# ET6801 register map
Vendor: ETMCU Inc.; File version: v0.0.1
CPU: CM7 r2p1, little endian, MPU, FPU, I-cache, D-cache, ITCM, DTCM, 4 interrupt priority bits
Registers are 32-bit, read-write, reset 0x0 unless marked. A register's access mark holds for its fields unless they carry their own. Offsets are from the block's base; [hi:lo] are bit positions; {n}, {i} and the like mark numbered series; <NAME> marks a mode.

## SYSC — Provide an overview of the purpose and functionality of the peripheral: sysc
Base 0x40400000
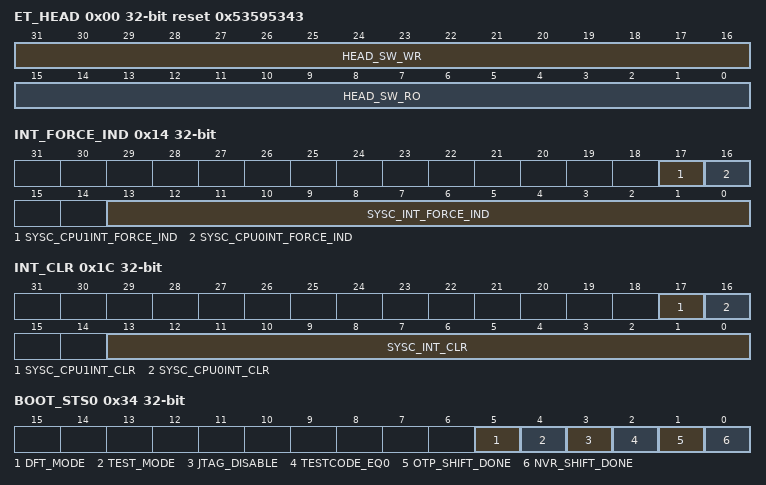
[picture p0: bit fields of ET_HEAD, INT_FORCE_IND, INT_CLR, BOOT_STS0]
0x00 ET_HEAD reset 0x53595343
  [31:16] HEAD_SW_WR — 软件测试读写寄存器，硬件无访问
  [15:0] HEAD_SW_RO ro — 软件只读上报寄存器，硬件无访问, SYSC的ASICII 码表示
0x04 INT_EN
  [13:0] SYSC_INT_EN — b0：取消使能SYSC逻辑中断； 'b1：表示使能SYSC逻辑中断； [0] :osc0_25m_los [1] :osc1_25m_los [2]:xo25m_los [3]:pll0_los [4]:pll0_unlock [5]:a2d_pmu_borh [6]:a2d_pmu_borh_warn [7]:a2d_pmu_ovrh [8]:a2d_pmu_borl [9]:a2d_pmu_borl_warn [10]:a2d_pmu_ovrl [11]:a2d_pmu_sysldo_ocp [12]:a2d_tsd_sync [13]:a2d_tsd_warn
0x08 CMPC_INT_EN
  [21:0] CMPC_INT_EN — b0：取消使能cmpc逻辑中断； 'b1：表示使能cpmc逻辑中断； [10]~[0]: cmpc_h_lpm_wkup10~cmpc_h_lpm_wkup0 [21]~[11]:cmpc_l_lpm_wkup10~cmpc_l_lpm_wkup0
0x0C INT_MASK
  [13:0] SYSC_INT_MASK — b0：取消屏蔽SYSC逻辑中断； 'b1：表示屏蔽SYSC逻辑中断； [0] :osc0_25m_los [1] :osc1_25m_los [2]:xo25m_los [3]:pll0_los [4]:pll0_unlock [5]:a2d_pmu_borh [6]:a2d_pmu_borh_warn [7]:a2d_pmu_ovrh [8]:a2d_pmu_borl [9]:a2d_pmu_borl_warn [10]:a2d_pmu_ovrl [11]:a2d_pmu_sysldo_ocp [12]:a2d_tsd_sync [13]:a2d_tsd_warn
0x10 CMPC_INT_MASK
  [21:0] CMPC_INT_MASK — b0：取消屏蔽CMPC逻辑中断； 'b1：表示屏蔽CMPC逻辑中断； [10]~[0]: cmpc_h_lpm_wkup10~cmpc_h_lpm_wkup0 [21]~[11]:cmpc_l_lpm_wkup10~cmpc_l_lpm_wkup0
0x14 INT_FORCE_IND
  [17] SYSC_CPU1INT_FORCE_IND — b1：表示强制产生相应的cpu1中断，硬件自清零
  [16] SYSC_CPU0INT_FORCE_IND — b1：表示强制产生相应的cpu0中断，硬件自清零
  [13:0] SYSC_INT_FORCE_IND — b1：表示强制产生相应的测试中断，硬件自清零 [0] :osc0_25m_los [1] :osc1_25m_los [2]:xo25m_los [3]:pll0_los [4]:pll0_unlock [5]:a2d_pmu_borh [6]:a2d_pmu_borh_warn [7]:a2d_pmu_ovrh [8]:a2d_pmu_borl [9]:a2d_pmu_borl_warn [10]:a2d_pmu_ovrl [11]:a2d_pmu_sysldo_ocp [12]:a2d_tsd_sync [13]:a2d_tsd_warn
0x18 CMPC_INT_FORCE_IND
  [21:0] CMPC_INT_FORCE_IND — b1：表示软件强制置起CMPC逻辑中断，硬件自清零； [10]~[0]: cmpc_h_lpm_wkup10~cmpc_h_lpm_wkup0 [21]~[11]:cmpc_l_lpm_wkup10~cmpc_l_lpm_wkup0
0x1C INT_CLR
  [17] SYSC_CPU1INT_CLR — b1：表示清除相应的cpu1中断状态，硬件自清零
  [16] SYSC_CPU0INT_CLR — b1：表示清除相应的cpu0中断状态，硬件自清零
  [13:0] SYSC_INT_CLR — b1：表示清除相应的中断状态，硬件自清零 [0] :osc0_25m_los [1] :osc1_25m_los [2]:xo25m_los [3]:pll0_los [4]:pll0_unlock [5]:a2d_pmu_borh [6]:a2d_pmu_borh_warn [7]:a2d_pmu_ovrh [8]:a2d_pmu_borl [9]:a2d_pmu_borl_warn [10]:a2d_pmu_ovrl [11]:a2d_pmu_sysldo_ocp [12]:a2d_tsd_sync [13]:a2d_tsd_warn
0x20 CMPC_INT_CLR
  [21:0] CMPC_INT_CLR — b1：表示清除相应的中断状态，硬件自清零 [10]~[0]: cmpc_h_lpm_wkup10~cmpc_h_lpm_wkup0 [21]~[11]:cmpc_l_lpm_wkup10~cmpc_l_lpm_wkup0
0x24 INT_RAW_RPT ro
  [13:0] SYSC_INT_RAW_RPT — 中断MASK前RAW 中断状态上报 'b0：表示中断MASK前无中断状态； 'b1：表示中断MASK前有中断状态； [0] :osc0_25m_los [1] :osc1_25m_los [2]:xo25m_los [3]:pll0_los [4]:pll0_unlock [5]:a2d_pmu_borh [6]:a2d_pmu_borh_warn [7]:a2d_pmu_ovrh [8]:a2d_pmu_borl [9]:a2d_pmu_borl_warn [10]:a2d_pmu_ovrl [11]:a2d_pmu_sysldo_ocp [12]:a2d_tsd_sync [13]:a2d_tsd_warn
0x28 CMPC_INT_RAW_RPT ro
  [21:0] CMPC_INT_RAW_RPT — 中断MASK前RAW 中断状态上报 'b0：表示中断MASK前无中断状态； 'b1：表示中断MASK前有中断状态； [0] :osc0_25m_los [1] :osc1_25m_los [2]:xo25m_los [3]:pll0_los [4]:pll0_unlock [5]:a2d_pmu_borh [6]:a2d_pmu_borh_warn [7]:a2d_pmu_ovrh [8]:a2d_pmu_borl [9]:a2d_pmu_borl_warn [10]:a2d_pmu_ovrl [11]:a2d_pmu_sysldo_ocp [12]:a2d_tsd_sync [13]:a2d_tsd_warn
0x2C INT_STATUS_RPT ro
  [13:0] SYSC_INT_STATUS_RPT — 中断MASK后中断状态上报 'b0：表示中断MASK后无中断状态； 'b1：表示中断MASK后有中断状态； [0] :osc0_25m_los [1] :osc1_25m_los [2]:xo25m_los [3]:pll0_los [4]:pll0_unlock [5]:a2d_pmu_borh [6]:a2d_pmu_borh_warn [7]:a2d_pmu_ovrh [8]:a2d_pmu_borl [9]:a2d_pmu_borl_warn [10]:a2d_pmu_ovrl [11]:a2d_pmu_sysldo_ocp [12]:a2d_tsd_sync [13]:a2d_tsd_warn
0x30 CMPC_INT_STATUS_RPT ro
  [21:0] CMPC_INT_STATUS_RPT — 中断MASK后中断状态上报 'b0：表示中断MASK后无中断状态； 'b1：表示中断MASK后有中断状态； [10]~[0]: cmpc_h_lpm_wkup10~cmpc_h_lpm_wkup0 [21]~[11]:cmpc_l_lpm_wkup10~cmpc_l_lpm_wkup0
0x34 BOOT_STS0 ro
  [5] DFT_MODE — 内部锁存后的dft_mode数据上报
  [4] TEST_MODE — 内部锁存后的test_mode数据上报
  [3] JTAG_DISABLE — 内部锁存后的jtag_disable数据上报
  [2] TESTCODE_EQ0 — 内部锁存后的testcode_eq0数据上报
  [1] OTP_SHIFT_DONE — 内部锁存后的otp_shift_done数据上报
  [0] NVR_SHIFT_DONE — 内部锁存后的nvr_shift_done数据上报
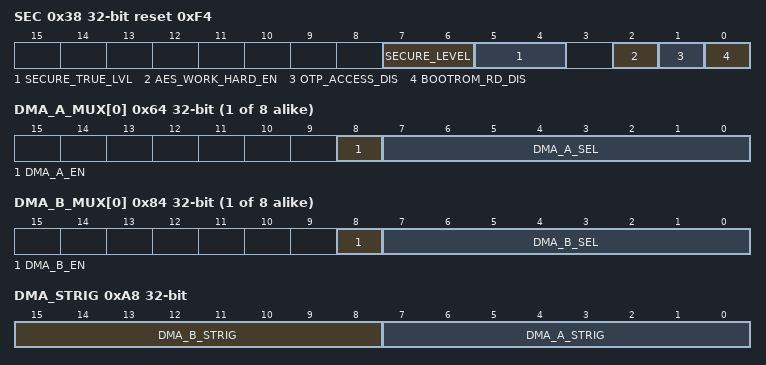
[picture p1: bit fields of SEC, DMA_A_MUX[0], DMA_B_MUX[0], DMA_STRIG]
0x38 SEC reset 0xF4
  [7:6] SECURE_LEVEL ro — otp输入的鉴权等级 2'b11:无需鉴权 2’b10/2’b01：需要鉴权，鉴权后所有调试接口都可访问 2’b00：禁止访问，所有调试接口都不可访问
  [5:4] SECURE_TRUE_LVL ro — 最终鉴权等级，根据test_code和secure_level得到： test_code != 32'b0 ： secure_true_lvl == 'b11； test_code == 32'b0 ： secure_true_lvl == secure_level； 2'b11:无需鉴权 2’b10/2’b01：需要鉴权，鉴权后所有调试接口都可访问 2’b00：禁止访问，所有调试接口都不可访问
  [2] AES_WORK_HARD_EN — 当boot程序自行判断AES是否需要关闭，在boot程序最后配置该寄存器；'b0: AES模块不能被访问；'b1: AES模块可以被正常访问； 该信号只能被写0，不能被写1；
  [1] OTP_ACCESS_DIS — 当boot程序自行判断otp信息在应用程序是否可以被操作（读/写/擦除），在boot程序最后配置该寄存器；'b0: otp信息能被操作（读/写/擦除）；'b1: otp信息不能被操作（读/写/擦除），读的时候返回固定值0； 该信号只能被写1，不能被写0；
  [0] BOOTROM_RD_DIS — 当boot程序检测到OTP信息：bootrom_rdp==1'b1 && test_code==32'd0，配置该寄存器为1；'b0: bootrom空间可以被正常访问；'b1: bootrom空间不被访问，输出被钳位到32'd0； 该信号只能被写1，不能被写0；
{0x3C+4i} CHIP_DIE{i} (i=0..7)
  [31:0] INFO — 芯片die参数信息[{32i+31}:{32i}]；bootrom从otp回读后写到该寄存器内，写操作受bootrom_rd_dis控制；
0x5C CHIP_VERSION0
  [31:0] PARTID — 芯片CHIP VERSION配置寄存器，仅bootrom阶段可写，硬件无任何操作
0x60 CHIP_VERSION1
  [31:0] PARTID — 芯片CHIP VERSION配置寄存器，仅bootrom阶段可写，硬件无任何操作
{0x64+4i} DMA_A_MUX[{i}] (i=0..7) — DMA_A_MUX%S
  [8] DMA_A_EN — AHB DMA0子通道的DMA选择使能 'b0：当前通道关闭选择使能，相应的dma_req和dma_single恒为0； 'b1：当前通道启用选择使能，按软件配置选择dma_req和dma_single输出。
  [7:0] DMA_A_SEL — AHB DMA0子通道的DMA选择： 0crc_dma_req 1fmac_rd_dma_req 2fmac_wr_dma_req 6~3sdfm0_dma_req[3:0] 10~7sdfm1_dma_req[3:0] 14~11sdfm2_dma_req[3:0] 18~15sdfm3_dma_req[3:0] 36~19epwm_dma_req[17:0] 37~54reserved 66~55 etim_dma_req[11:0] 70~67sarc0_dma_req[3:0] 71ADCAEVT 75~72sarc1_dma_req[3:0] 76ADCBEVT 80~77sarc2_dma_req[3:0] 81ADCCEVT 82cmpc0_dma_dac0_req 83cmpc0_dma_dac1_req 84cmpc1_dma_dac0_req 85cmpc1_dma_dac1_req 86cmpc2_dma_dac0_req 87cmpc2_dma_dac1_req 88cmpc3_dma_dac0_req 89cmpc3_dma_dac1_req 90cmpc4_dma_dac0_req 91cmpc4_dma_dac1_req 92cmpc5_dma_dac0_req 93cmpc5_dma_dac1_req 94cmpc6_dma_dac0_req 95cmpc6_dma_dac1_req 96cmpc7_dma_dac0_req 97cmpc7_dma_dac1_req 98cmpc8_dma_dac0_req 99cmpc8_dma_dac1_req 100cmpc9_dma_dac0_req 101cmpc9_dma_dac1_req 102cmpc10_dma_dac0_req 103cmpc10_dma_dac1_req 104stm0_dma_req 105stm1_dma_req 106stm2_dma_req 107stm3_dma_req 108stm4_dma_req 109stm5_dma_req 110bdac0_dma_req 111bdac1_dma_req 112aes_wr_dma_req 113aes_rd_dma_req 114wag_dma_req 115XINT0 116XINT1 117XINT2 118XINT3 119XINT4 120CLB0_INT 121CLB1_INT 122CLB2_INT 123CLB3_INT 124CLB4_INT 125CLB5_INT 126LIN0_TXDMA 127LIN0_RXDMA 128LIN1_TXDMA 129LIN1_RXDMA 130-191reserved 192uart0_dma_tx_req 193uart0_dma_rx_req 194uart1_dma_tx_req 195uart1_dma_rx_req 196uart2_dma_tx_req 197uart2_dma_rx_req 198uart3_dma_tx_req 199uart3_dma_rx_req 200uart4_dma_tx_req 201uart4_dma_rx_req 202uart5_dma_tx_req 203uart5_dma_rx_req 204uart6_dma_tx_req 205uart6_dma_rx_req 206uart7_dma_tx_req 207uart7_dma_rx_req 208i2c0_dma_tx_req 209i2c0_dma_rx_req 210i2c1_dma_tx_req 211i2c1_dma_rx_req 212i2c2_dma_tx_req 213i2c2_dma_rx_req 214spi0_dma_tx_req 215spi0_dma_rx_req 216spi1_dma_tx_req 217spi1_dma_rx_req 218spi2_dma_tx_req 219spi2_dma_rx_req 220spi3_dma_tx_req 221spi3_dma_rx_req 222can0_dma_tx_req 223can0_dma_rx_req 224can1_dma_tx_req 225can1_dma_rx_req 226can2_dma_tx_req 227can2_dma_rx_req 228qspi_dma_tx_req 229qspi_dma_rx_req 230~255reserved
{0x84+4i} DMA_B_MUX[{i}] (i=0..7) — DMA_B_MUX%S
  [8] DMA_B_EN — AHB DMA1子通道的DMA选择使能 'b0：当前通道关闭选择使能，相应的dma_req和dma_single恒为0； 'b1：当前通道启用选择使能，按软件配置选择dma_req和dma_single输出。
  [7:0] DMA_B_SEL — AHB DMA1子通道的DMA选择，其选项与CFG_DMA_A_MUX [cfg_dma_a_sel]的选项一致。
0xA4 DMA_MUX_MK reset 0xFFFF
  [15:0] DMA_MUX_FIN_MSK — 每个bit对应一个DMA通道，BIT0对应AHB DMA0的通道0，......，BIT7对应AHB DMA0的通道7，BIT8对应AHB DMA1的通道0，......，BIT15对应AHB DMA1的通道7； 'b0：使用dma_ack和dma_finish信号联合控制DMA传输，支持一次hac （寄存器读写）dma触发，响应多个dma_ack，实现多个burst传输（直至出现dma_finish）； 'b1：屏蔽dma_finish信号，仅使用dma_ack信号控制DMA传输，一次触发，仅响应一次dma_ack信号（ET6001模式）
0xA8 DMA_STRIG
  [15:8] DMA_B_STRIG wo — 软件置1强制DMA1 8通道进行一次触发,硬件自清零，该触发功能与cfg_dma_b_sel选择后的触发信号功能相同，注意：若cfg_dma_b_sel配置大于191，则强制触发无效。 cfg_dma_b_strig[7:0]分别对应DMA1的7~0通道；
  [7:0] DMA_A_STRIG wo — 软件置1强制DMA0 8通道进行一次触发,硬件自清零，该触发功能与cfg_dma_a_sel0~7选择后的触发信号功能相同。注意：若cfg_dma_b_sel配置大于191，则强制触发无效。 cfg_dma_a_strig[7:0]分别对应DMA0的7~0通道；
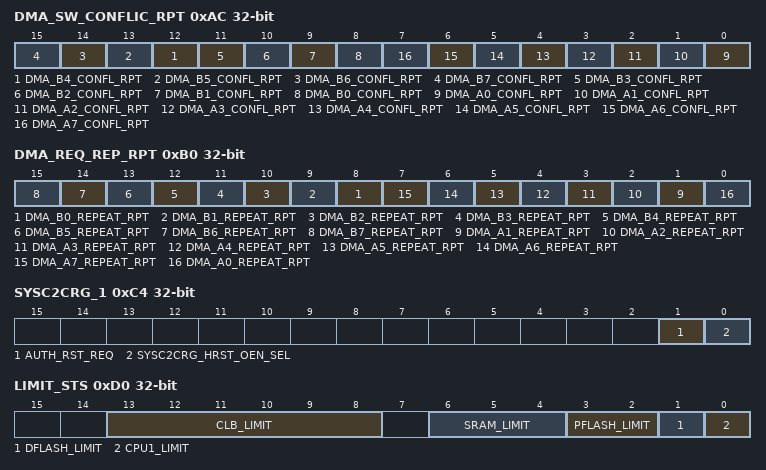
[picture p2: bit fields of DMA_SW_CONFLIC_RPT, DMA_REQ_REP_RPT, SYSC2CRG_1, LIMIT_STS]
0xAC DMA_SW_CONFLIC_RPT
  [n+8] DMA_B{n}_CONFL_RPT (n=4..7) — AHB DMA1的{n}通道，切换DMA选择时，dma_req或dma_single为高，当前状态寄存器置1，写1清，软件做调试用 软件写1清。
  [11] DMA_B3_CONFL_RPT — AHB DMA0的3通道，切换DMA选择时，dma_req或dma_single为高，当前状态寄存器置1，写1清，软件做调试用 软件写1清。
  [10] DMA_B2_CONFL_RPT — AHB DMA1的2通道，切换DMA选择时，dma_req或dma_single为高，当前状态寄存器置1，写1清，软件做调试用 软件写1清。
  [9] DMA_B1_CONFL_RPT — AHB DMA1的1通道，切换DMA选择时，dma_req或dma_single为高，当前状态寄存器置1，写1清，软件做调试用 软件写1清。
  [8] DMA_B0_CONFL_RPT — AHB DMA1的0通道，切换DMA选择时，dma_req或dma_single为高，当前状态寄存器置1，写1清，软件做调试用 软件写1清。
  [n] DMA_A{n}_CONFL_RPT (n=0..7) — AHB DMA0的{n}通道，切换DMA选择时，dma_req或dma_single为高，当前状态寄存器置1，写1清，软件做调试用 软件写1清。
0xB0 DMA_REQ_REP_RPT
  [n+8] DMA_B{n}_REPEAT_RPT (n=0..7) — AHB DMA1的{n}通道，在一次HAC的DMA请求未结束前，又出现新的HAC DMA请求触发源，则当前寄存器位锁存为高电平，软件写1清。
  [n] DMA_A{n}_REPEAT_RPT (n=1..7) — AHB DMA0的{n}通道，在一次HAC的DMA请求未结束前，又出现新的HAC DMA请求触发源，则当前寄存器位锁存为高电平，软件写1清。
  [0] DMA_A0_REPEAT_RPT — AHB DMA0的0通道，在一次HAC的DMA请求未结束前，又出现新的HAC DMA请求触发源，则当前寄存器位锁存为高电平，软件写1清。当前寄存器地址中，含repeat字样的重复告警上报只针对cfg_dma_a/b_sel的取值大于等于19，小于等于129的场景（HAC进行寄存器读写的场景）。
0xB4 CPU0_BTADDR reset 0x20500000
  [31:0] SYSC_CPU0_INITVTOR — CPU0启动地址
0xB8 CPU1_BTADDR
  [31:0] SYSC_CPU1_INITVTOR — CPU1启动地址
0xBC NV
  [31:0] LOCK — POR时钟域关键寄存器锁定使能；当配置为非0x12345678时，可上锁对特定寄存器的配置；
0xC0 SYSC2CRG
  [31:0] SOFTRST_N — 全局软复位；当配置为0x45670123时，产生全局软复位信号（1'b0，低电平有效）到CRG模块，CRG随机进行芯片全局软复位；CRG进行全局软复位后，该配置自动被清成default值，也就是全局软复位信号被复位成1'b1:
0xC4 SYSC2CRG_1
  [1] AUTH_RST_REQ — jauth模块的软复位请求信号。1'b1:软复位请求有效 1'b0:软复位请求无效
  [0] SYSC2CRG_HRST_OEN_SEL — 选择芯片的POR复位和WDG复位输出到芯片HRD_RST_N管脚可观测，其观测值是否有效。 1'b0:观测值有效 1'b1:观测值无效
0xC8 SYSC2SPWM
  [17:0] BC_MAP_INFO — spwm扩展配置映射信息；18bit配置对应18个spwm，如bit[0]对应spwm0，bit[1]对应spwm1......bit[17]对应spwm17; 'b0：在配置spwm_bc时，不会同时配置到该spwm； 'b1：在配置spwm_bc时，会同时配置到该spwm； 准静态配置：该配置完成后，spwm才可能打开使能进行工作；
0xCC BOOT
  [0] PROC_IND — 启动过程说明； 'b0：冷启动； 'b1：热启动； bootrom根据这个bit来判断走冷启动流程还是热启动流程，在bootrom的最后，将该bit修改为1；
0xD0 LIMIT_STS ro
  [13:8] CLB_LIMIT — 信号含义，clb内共有6个clb_title，每个bit表示一个clb的clb_title使能，1表示使能，0表示不使能：clb_limit[0]:clb_title0的使能； clb_limit[1]:clb_title1的使能； clb_limit[2]:clb_title2的使能； clb_limit[3]:clb_title3的使能； clb_limit[4]:clb_title4的使能； clb_limit[5]:clb_title5的使能；
  [6:4] SRAM_LIMIT — 寄存器含义： 3'b000:SRAM256KB+256KB 3'b001:SRAM 128KB+128KB others：SRAM 256KB + 256KB注意：sram在各个限制模式下，起始地址均是0x2040_0000 不限定模式下： SRAM0起始地址0x2040_0000； SRAM1起始地址0x2044_0000； 限定模式下： SRAM0起始地址0x2040_0000； SRAM1起始地址0x2042_0000；
  [3:2] PFLASH_LIMIT — 信号含义： 2'b00:pflash空间2MB空间不做空间访问限制； 2'b01:pflash 空间限制为1MB； 2'b10:pflash 空间限制为512KB; others:pflash 空间不限制，为2MB; 注意：pflash限定与否，起始地址不变，软件看到的pflash系统地址起始地址都是0x8000_0000
  [1] DFLASH_LIMIT — 信号含义： 1'b0:dflash main 空间128KB总线不做访问限制； 1'b1:dflash main 空间128KB总线限制访问注意：dflash限定与否，其起始地址均不变，均为0x0808_0000
  [0] CPU1_LIMIT — 信号含义： 1'b0:cpu1 限定； 1'b1:cpu1 不限定；
{0xD4+4i} BLBX{i} (i=0..15)
  [31:0] REG_BX — 黑匣子寄存器，只可CPU读写，POR复位；硬件无任何操作；受sysc_nv_lock寄存器锁定；
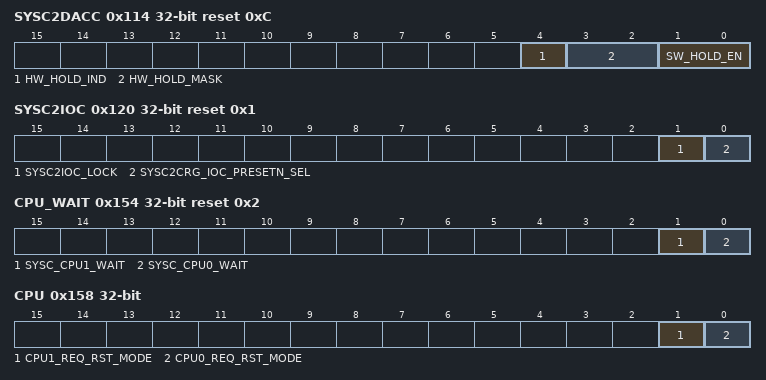
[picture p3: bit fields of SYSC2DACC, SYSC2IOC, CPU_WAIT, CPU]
0x114 SYSC2DACC reset 0xC
  [4] HW_HOLD_IND — DAC输出保持状态； 'b0：DAC输出正常，根据DAC配置进行输出； 'b1：DAC输出保持不变；软复位重新启动，APP程序需要根据软硬件hold_ind判断是否进行重新配置DAC参数，以及对hold_ind进行清零；软件写1清。
  [3:2] HW_HOLD_MASK — DACC硬件保持屏蔽信号； 'b0：DACC硬件保持屏蔽功能关闭； 'b1：DACC硬件保持屏蔽功能打开； 受sysc_nv_lock寄存器锁定；
  [1:0] SW_HOLD_EN — DACC软件强制保持使能； 'b0：DACC软件强制保持使能关闭； 'b1：DACC软件强制保持使能打开； 受sysc_nv_lock寄存器锁定；
0x118 FLS
  [0] BANKSWAP — Pflash高低地址映射内容调换选择； 'b0:不调换； 'b1:调换； 根据LIMIT_STS.pflash_limits完成高低地址内容调换，如在不限定方案表达的含义为： ‘b0:正常使用pflash的2M地址空间； ’b1：pflash的高1M地址空间与低1M空间调换； 每次复位，BOOTROM从dFlash NVR读取对应信息，写到这个寄存器；
0x11C EFC
  [1:0] DPD — 对EFC的Flash颗粒进行DPD控制；bit[0]对应pflash-efc1，bit[1]对应dflash-efc2，bit[2]对应efc2； 'b0：Flash颗粒正常工作； 'b1：Flash颗粒工作到DPD模式；
0x120 SYSC2IOC reset 0x1
  [1] SYSC2IOC_LOCK — IOC的配置lock指示； 'b0: IOC可以正常配置； 'b1: IOC不能被配置；
  [0] SYSC2CRG_IOC_PRESETN_SEL — IOC 复位选择 'b0 -- 受sys复位（包含por复位） 'b1 -- 仅受por复位
0x124 CLK_SCNT
  [0] SEL_IN — syscnt时钟选择信号 'b0：内部选择后的osc25M时钟；（默认） 'b1：XO25M时钟；
0x128 SCNT
  [0] HALT_MODE_EN — syscnt halt模式使能； 'b0：syscnt halt模式使能关闭； 'b1：syscnt halt模式使能打开；
{0x12C+4i} STM{i} ro (i=0..5)
  [31:0] SYSC_ERG_CNT — 紧急故障触发源锁定当前STM{i}值
0x144 CHIP_RSVED_0
  [31:0] SYS — 预留寄存器配置，给软件使用，硬件不做处理, 当前寄存器表示对应bit[31:0]；
0x148 CHIP_RSVED_1
  [31:0] SYS — 预留寄存器配置，给软件使用，硬件不做处理, 当前寄存器表示对应bit[63:32]；
0x14C CHIP_RSVED_1_0
  [31:0] POR — 预留寄存器配置，给软件使用，硬件不做处理, 当前寄存器表示对应bit[31:0]；
0x150 CHIP_RSVED_1_1
  [31:0] POR — 预留寄存器配置，给软件使用，硬件不做处理, 当前寄存器表示对应bit[63:32]；
0x154 CPU_WAIT reset 0x2
  [1] SYSC_CPU1_WAIT — CPU1wait设置 'b1:cpu1处于wait状态 ‘b0：cpu1不处于wait状态
  [0] SYSC_CPU0_WAIT — CPU0wait设置 'b1:cpu0处于wait状态 ‘b0：cpu0不处于wait状态
0x158 CPU
  [1] CPU1_REQ_RST_MODE — CPU复位申请，产生哪种模式的复位； 'b0：产生全局软复位； 'b1：只产生CPU1系统复位
  [0] CPU0_REQ_RST_MODE — CPU复位申请，产生哪种模式的复位； 'b0：产生全局软复位； 'b1：只产生CPU0系统复位
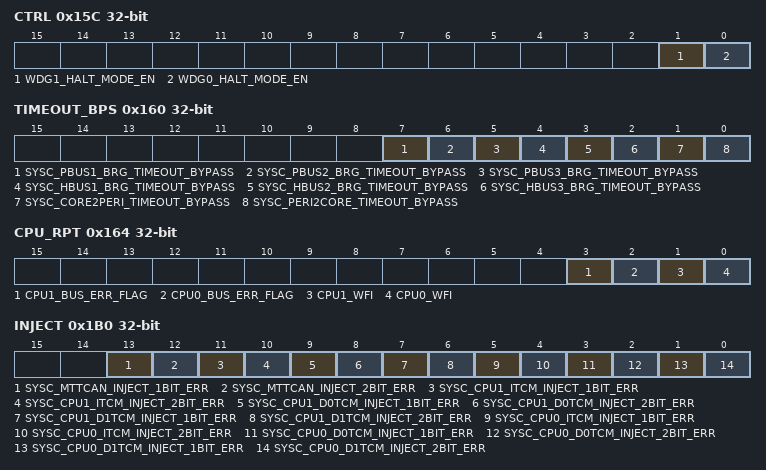
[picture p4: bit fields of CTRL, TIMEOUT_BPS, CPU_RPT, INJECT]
0x15C CTRL
  [1] WDG1_HALT_MODE_EN — 看门狗1的halt模式使能开关； 'b0：看门狗0的halt模式使能关闭； 'b1：看门狗0的halt模式使能打开；
  [0] WDG0_HALT_MODE_EN — 看门狗0的halt模式使能开关； 'b0：看门狗0的halt模式使能关闭； 'b1：看门狗0的halt模式使能打开；
0x160 TIMEOUT_BPS
  [7] SYSC_PBUS1_BRG_TIMEOUT_BYPASS — APB BUS1的timeout旁路使能开关； 'b0：APB BUS1的timeout旁路使能关闭； 'b1：APB BUS1的timeout旁路使能打开；
  [6] SYSC_PBUS2_BRG_TIMEOUT_BYPASS — APB BUS2的timeout旁路使能开关； 'b0：APB BUS2的timeout旁路使能关闭； 'b1：APB BUS2的timeout旁路使能打开；
  [5] SYSC_PBUS3_BRG_TIMEOUT_BYPASS — APB BUS3的timeout旁路使能开关； 'b0：APB BUS3的timeout旁路使能关闭； 'b1：APB BUS3的timeout旁路使能打开；
  [4] SYSC_HBUS1_BRG_TIMEOUT_BYPASS — AHB BUS1的timeout旁路使能开关； 'b0：AHB BUS1的timeout旁路使能关闭； 'b1：AHB BUS1的timeout旁路使能打开；
  [3] SYSC_HBUS2_BRG_TIMEOUT_BYPASS — AHB BUS2的timeout旁路使能开关； 'b0：AHB BUS2的timeout旁路使能关闭； 'b1：AHB BUS2的timeout旁路使能打开；
  [2] SYSC_HBUS3_BRG_TIMEOUT_BYPASS — AHB BUS3的timeout旁路使能开关； 'b0：AHB BUS3的timeout旁路使能关闭； 'b1：AHB BUS3的timeout旁路使能打开；
  [1] SYSC_CORE2PERI_TIMEOUT_BYPASS — core2peri的timeout旁路使能开关； 'b0：core2peri的timeout旁路使能关闭； 'b1：core2peri的timeout旁路使能打开；
  [0] SYSC_PERI2CORE_TIMEOUT_BYPASS — peri2core的timeout旁路使能开关； 'b0：AHB BUS3的timeout旁路使能关闭； 'b1：AHB BUS3的timeout旁路使能打开；
0x164 CPU_RPT ro
  [3] CPU1_BUS_ERR_FLAG — CPU1的总线错误状态 'b0：cpu1不处于总线错误状态； 'b1：cpu1处于总线错误状态；
  [2] CPU0_BUS_ERR_FLAG — CPU0的总线错误状态； 'b0：cpu0不处于总线错误状态； 'b1：cpu0处于总线错误状态；
  [1] CPU1_WFI — CPU1的wfi状态； 'b0：cpu不处于wfi状态； 'b1：cpu处于wfi状态；
  [0] CPU0_WFI — CPU的wfi状态； 'b0：cpu不处于wfi状态； 'b1：cpu处于wfi状态；
0x168 CTRLBUS_0 reset 0x9A9D1
  [31:0] SYSC_XSRAM0_CTRLBUS — 1rw类型sram, 当前寄存器表示对应bit[31:0]；
0x16C CTRLBUS_1
  [31:0] SYSC_XSRAM0_CTRLBUS — 1rw类型sram, 当前寄存器表示对应bit[63:32]；
0x170 CTRLBUS_1_0 reset 0x9A9D1
  [31:0] SYSC_XSRAM1_CTRLBUS — 1rw类型sram, 当前寄存器表示对应bit[31:0]；
0x174 CTRLBUS_1_1
  [31:0] SYSC_XSRAM1_CTRLBUS — 1rw类型sram, 当前寄存器表示对应bit[63:32]；
0x178 CTRLBUS_2_0 reset 0x9A9D1
  [31:0] SYSC_BOOTROM_CTRLBUS — rom类型, 当前寄存器表示对应bit[31:0]；
0x17C CTRLBUS_2_1
  [31:0] SYSC_BOOTROM_CTRLBUS — rom类型, 当前寄存器表示对应bit[63:32]；
0x180 CTRLBUS_3_0 reset 0x9A9D1
  [31:0] SYSC_CAN_MSG_CTRLBUS — 1rw类型sram, 当前寄存器表示对应bit[31:0]；
0x184 CTRLBUS_3_1
  [31:0] SYSC_CAN_MSG_CTRLBUS — 1rw类型sram, 当前寄存器表示对应bit[63:32]；
{0x168+8i} CTRLBUS_{i}_0 reset 0x9A9D1 (i=4..6)
  [31:0] SYSC_SARC{i-4}_CTRLBUS — 1r1w/1rw类型sram, 当前寄存器表示对应bit[31:0]；
{0x16C+8i} CTRLBUS_{i}_1 (i=4..6)
  [31:0] SYSC_SARC{i-4}_CTRLBUS — 1r1w/1rw类型sram, 当前寄存器表示对应bit[63:32]；
0x1A0 CTRLBUS_7_0 reset 0x9A9D1
  [31:0] SYSC_FMAC_CTRLBUS — 1rw类型sram, 当前寄存器表示对应bit[31:0]；
0x1A4 CTRLBUS_7_1
  [31:0] SYSC_FMAC_CTRLBUS — 1rw类型sram, 当前寄存器表示对应bit[63:32]；
0x1A8 CTRLBUS_8_0 reset 0x9A9D1
  [31:0] SYSC_ETF_CTRLBUS — 1rw类型sram, 当前寄存器表示对应bit[31:0]；
0x1AC CTRLBUS_8_1
  [31:0] SYSC_ETF_CTRLBUS — 1rw类型sram, 当前寄存器表示对应bit[63:32]；
0x1B0 INJECT
  [13] SYSC_MTTCAN_INJECT_1BIT_ERR — CAN的ECC 1bit错误注入配置 'b0： 不注入； 'b1： 注入1bit错误；
  [12] SYSC_MTTCAN_INJECT_2BIT_ERR — CAN的ECC 2bit错误注入配置 'b0： 不注入； 'b1： 注入1bit错误；
  [11] SYSC_CPU1_ITCM_INJECT_1BIT_ERR — cpu itcm的ECC 1bit错误注入配置 'b0： 不注入； 'b1： 注入1bit错误；
  [10] SYSC_CPU1_ITCM_INJECT_2BIT_ERR — cpu itcm的ECC 2bit错误注入配置 'b0： 不注入； 'b1： 注入1bit错误；
  [9] SYSC_CPU1_D0TCM_INJECT_1BIT_ERR — cpu d0tcm的ECC 1bit错误注入配置 'b0： 不注入； 'b1： 注入1bit错误；
  [8] SYSC_CPU1_D0TCM_INJECT_2BIT_ERR — cpu d0tcm的ECC 2bit错误注入配置 'b0： 不注入； 'b1： 注入1bit错误；
  [7] SYSC_CPU1_D1TCM_INJECT_1BIT_ERR — cpu d1tcm的ECC 1bit错误注入配置 'b0： 不注入； 'b1： 注入1bit错误；
  [6] SYSC_CPU1_D1TCM_INJECT_2BIT_ERR — cpu d1tcm的ECC 2bit错误注入配置 'b0： 不注入； 'b1： 注入1bit错误；
  [5] SYSC_CPU0_ITCM_INJECT_1BIT_ERR — cpu itcm的ECC 1bit错误注入配置 'b0： 不注入； 'b1： 注入1bit错误；
  [4] SYSC_CPU0_ITCM_INJECT_2BIT_ERR — cpu itcm的ECC 2bit错误注入配置 'b0： 不注入； 'b1： 注入1bit错误；
  [3] SYSC_CPU0_D0TCM_INJECT_1BIT_ERR — cpu d0tcm的ECC 1bit错误注入配置 'b0： 不注入； 'b1： 注入1bit错误；
  [2] SYSC_CPU0_D0TCM_INJECT_2BIT_ERR — cpu d0tcm的ECC 2bit错误注入配置 'b0： 不注入； 'b1： 注入1bit错误；
  [1] SYSC_CPU0_D1TCM_INJECT_1BIT_ERR — cpu d1tcm的ECC 1bit错误注入配置 'b0： 不注入； 'b1： 注入1bit错误；
  [0] SYSC_CPU0_D1TCM_INJECT_2BIT_ERR — cpu d1tcm的ECC 2bit错误注入配置 'b0： 不注入； 'b1： 注入1bit错误；
0x1B4 ECCEN
  [0] SYSC_MTTCAN_ECC_EN — CAN0的ECC 使能配置 'b0： ECC不使能； 'b1： ECC使能；
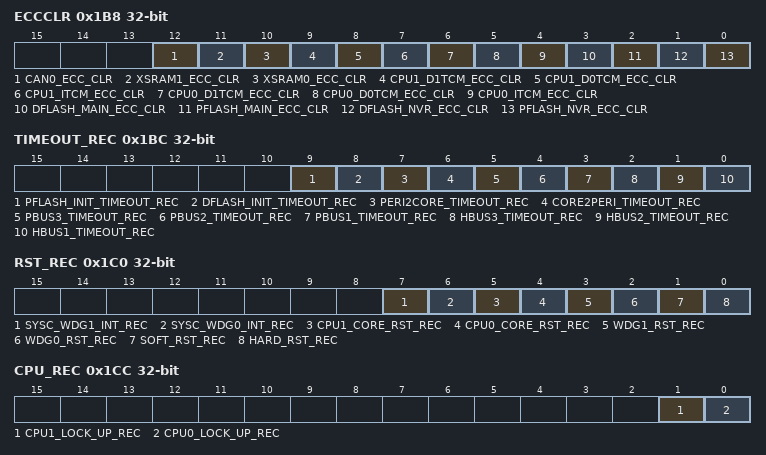
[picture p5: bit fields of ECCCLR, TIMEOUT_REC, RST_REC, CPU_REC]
0x1B8 ECCCLR
  [12] CAN0_ECC_CLR — can0 ECC错误指示清零信号，同时清零2bit错误和1bit错误'b0：ECC错误指示不做清零动作； 'b1：ECC错误指示清零动作， 硬件会对本控制bit自动清零；
  [11] XSRAM1_ECC_CLR — sram1 ECC错误指示清零信号，同时清零2bit错误和1bit错误 'b0：ECC错误指示不做清零动作； 'b1：ECC错误指示清零动作， 硬件会对本控制bit自动清零；
  [10] XSRAM0_ECC_CLR — sram0 ECC错误指示清零信号，同时清零2bit错误和1bit错误 'b0：ECC错误指示不做清零动作； 'b1：ECC错误指示清零动作， 硬件会对本控制bit自动清零；
  [9] CPU1_D1TCM_ECC_CLR — CPU d1tcm ECC错误指示清零信号，同时清零2bit错误和1bit错误 'b0：ECC错误指示不做清零动作； 'b1：ECC错误指示清零动作， 硬件会对本控制bit自动清零；
  [8] CPU1_D0TCM_ECC_CLR — CPU d0tcm ECC错误指示清零信号，同时清零2bit错误和1bit错误 'b0：ECC错误指示不做清零动作； 'b1：ECC错误指示清零动作， 硬件会对本控制bit自动清零；
  [7] CPU1_ITCM_ECC_CLR — CPU itcm ECC错误指示清零信号，同时清零2bit错误和1bit错误 'b0：ECC错误指示不做清零动作； 'b1：ECC错误指示清零动作， 硬件会对本控制bit自动清零；
  [6] CPU0_D1TCM_ECC_CLR — CPU d1tcm ECC错误指示清零信号，同时清零2bit错误和1bit错误 'b0：ECC错误指示不做清零动作； 'b1：ECC错误指示清零动作， 硬件会对本控制bit自动清零；
  [5] CPU0_D0TCM_ECC_CLR — CPU d0tcm ECC错误指示清零信号，同时清零2bit错误和1bit错误'b0：ECC错误指示不做清零动作；'b1：ECC错误指示清零动作，硬件会对本控制bit自动清零；
  [4] CPU0_ITCM_ECC_CLR — CPU itcm ECC错误指示清零信号，同时清零2bit错误和1bit错误 'b0：ECC错误指示不做清零动作； 'b1：ECC错误指示清零动作， 硬件会对本控制bit自动清零；
  [3] DFLASH_MAIN_ECC_CLR — EFC2 Main ECC错误指示清零信号，同时清零2bit错误和1bit错误 'b0：ECC错误指示不做清零动作； 'b1：ECC错误指示清零动作，硬件会对本控制bit自动清零；
  [2] PFLASH_MAIN_ECC_CLR — EFC0 Main ECC错误指示清零信号，同时清零2bit错误和1bit错误'b0：ECC错误指示不做清零动作；'b1：ECC错误指示清零动作，硬件会对本控制bit自动清零；
  [1] DFLASH_NVR_ECC_CLR — EFC2 NVR ECC错误指示清零信号，同时清零2bit错误和1bit错误 'b0：ECC错误指示不做清零动作； 'b1：ECC错误指示清零动作， 硬件会对本控制bit自动清零；
  [0] PFLASH_NVR_ECC_CLR — EFC1 NVR ECC错误指示清零信号，同时清零2bit错误和1bit错误 'b0：ECC错误指示不做清零动作； 'b1：ECC错误指示清零动作，硬件会对本控制bit自动清零；
0x1BC TIMEOUT_REC
  [9] PFLASH_INIT_TIMEOUT_REC — PFlash0初始化失败记录； 'b0：没有发生过PFlash0初始化失败； 'b1：发生过PFlash0初始化失败； 软件对本bit域写1，表示清除该历史记录；软件写1清。
  [8] DFLASH_INIT_TIMEOUT_REC — DFlash初始化失败记录； 'b0：没有发生过DFlash初始化失败； 'b1：发生过DFlash初始化失败； 软件对本bit域写1，表示清除该历史记录；软件写1清。
  [7] PERI2CORE_TIMEOUT_REC — peri2core_timeout历史记录； 'b0：没有发生过peri2core timeout； 'b1：发生过peri2core timeout； 软件对本bit域写1，表示清除该历史记录；软件写1清。
  [6] CORE2PERI_TIMEOUT_REC — core2peri_timeout历史记录； 'b0：没有发生过core2peri timeout； 'b1：发生过core2peri timeout； 软件对本bit域写1，表示清除该历史记录；软件写1清。
  [5] PBUS3_TIMEOUT_REC — pbus3_timeout历史记录； 'b0：没有发生过pbus3 timeout； 'b1：发生过pbus3 timeout； 软件对本bit域写1，表示清除该历史记录；软件写1清。
  [4] PBUS2_TIMEOUT_REC — pbus2_timeout历史记录； 'b0：没有发生过pbus2 timeout； 'b1：发生过pbus2 timeout； 软件对本bit域写1，表示清除该历史记录；软件写1清。
  [3] PBUS1_TIMEOUT_REC — pbus1_timeout历史记录； 'b0：没有发生过pbus1 timeout； 'b1：发生过pbus1 timeout； 软件对本bit域写1，表示清除该历史记录；软件写1清。
  [2] HBUS3_TIMEOUT_REC — hbus3_timeout历史记录；'b0：没有发生过hbus3 timeout；'b1：发生过hbus3 timeout；软件对本bit域写1，表示清除该历史记录；软件写1清。
  [1] HBUS2_TIMEOUT_REC — hbus2_timeout历史记录； 'b0：没有发生过hbus2 timeout； 'b1：发生过hbus2 timeout； 软件对本bit域写1，表示清除该历史记录；软件写1清。
  [0] HBUS1_TIMEOUT_REC — hbus1_timeout历史记录；'b0：没有发生过hbus1 timeout；'b1：发生过hbus1 timeout；软件对本bit域写1，表示清除该历史记录；软件写1清。
0x1C0 RST_REC
  [7] SYSC_WDG1_INT_REC — 看门狗1中断历史记录； 'b0：没有发生过看门狗1中断； 'b1：发生过看门狗1中断； 软件对本bit域写1，表示清除该历史记录；软件写1清。
  [6] SYSC_WDG0_INT_REC — 看门狗0中断历史记录； 'b0：没有发生过看门狗0中断； 'b1：发生过看门狗0中断； 软件对本bit域写1，表示清除该历史记录；软件写1清。
  [5] CPU1_CORE_RST_REC — CPU1复位请求历史记录； 'b0：没有发生过CPU1复位请求； 'b1：发生过CPU1复位请求； 软件对本bit域写1，表示清除该历史记录；软件写1清。
  [4] CPU0_CORE_RST_REC — CPU0复位请求历史记录； 'b0：没有发生过CPU0复位请求； 'b1：发生过CPU0复位请求； 软件对本bit域写1，表示清除该历史记录；软件写1清。
  [3] WDG1_RST_REC — 看门狗1复位请求历史记录； 'b0：没有发生过看门狗1复位请求； 'b1：发生过看门狗1复位请求； 软件对本bit域写1，表示清除该历史记录；软件写1清。
  [2] WDG0_RST_REC — 看门狗0复位请求历史记录； 'b0：没有发生过看门狗0复位请求； 'b1：发生过看门狗0复位请求； 软件对本bit域写1，表示清除该历史记录；软件写1清。
  [1] SOFT_RST_REC — 全局软复位历史记录； 'b0：没有发生过全局软复位； 'b1：发生过全局软复位； 软件对本bit域写1，表示清除该历史记录；软件写1清。
  [0] HARD_RST_REC — 管脚复位历史记录； 'b0：没有发生过管脚硬复位； 'b1：发生过管脚硬复位； 软件对本bit域写1，表示清除该历史记录；软件写1清。
0x1C4 FLS_REC ro
  [23:0] DFLASH_STATE_REC — DFlash状态机信息，该信息是使用dflash_init_timeout锁存的状态信息。芯片内部debug信息。
0x1C8 FLS_REC_1 ro
  [23:0] PFLASH_STATE_REC — PFlash0状态机信息，该信息是使用pflash0_init_timeout锁存的状态信息。
0x1CC CPU_REC
  [1] CPU1_LOCK_UP_REC — CPU1死锁状态记录； 'b0：没有发生过CPU1死锁； 'b1：发生过CPU1死锁； 软件对本bit域写1，表示清除该历史记录； 软件写1清。
  [0] CPU0_LOCK_UP_REC — CPU0死锁状态记录； 'b0：没有发生过CPU0死锁； 'b1：发生过CPU0死锁； 软件对本bit域写1，表示清除该历史记录； 软件写1清。
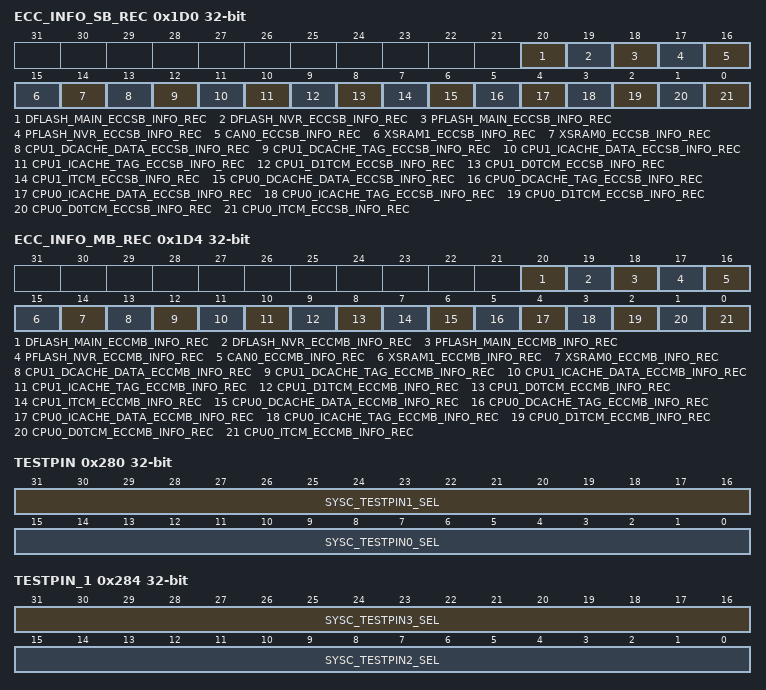
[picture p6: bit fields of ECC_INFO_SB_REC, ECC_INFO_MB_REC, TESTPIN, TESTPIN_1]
0x1D0 ECC_INFO_SB_REC ro
  [20] DFLASH_MAIN_ECCSB_INFO_REC — DFlash main array ECC信息历史记录，单比特错误； 'b0：没有发生过ECC错误； 'b1：发生过ECC错误；对应ecc_clr配置才能清除该历史记录；
  [19] DFLASH_NVR_ECCSB_INFO_REC — Flash NVR ECC信息历史记录，单比特错误； 'b0：没有发生过ECC错误； 'b1：发生过ECC错误； 对应ecc_clr配置才能清除该历史记录；
  [18] PFLASH_MAIN_ECCSB_INFO_REC — PFlash0 main array ECC信息历史记录，单比特错误； 'b0：没有发生过ECC错误； 'b1：发生过ECC错误； 对应ecc_clr配置才能清除该历史记录；
  [17] PFLASH_NVR_ECCSB_INFO_REC — Flash NVR ECC信息历史记录，单比特错误； 'b0：没有发生过ECC错误； 'b1：发生过ECC错误； 对应ecc_clr配置才能清除该历史记录；
  [16] CAN0_ECCSB_INFO_REC — AXI SRAM0 ECC信息历史记录，单比特错误； 'b0：没有发生过ECC错误； 'b1：发生过ECC错误； 对应ecc_clr配置才能清除该历史记录；
  [15] XSRAM1_ECCSB_INFO_REC — AXI SRAM1 ECC信息历史记录，单比特错误； 'b0：没有发生过ECC错误； 'b1：发生过ECC错误； 对应ecc_clr配置才能清除该历史记录；
  [14] XSRAM0_ECCSB_INFO_REC — AXI SRAM0 ECC信息历史记录，单比特错误； 'b0：没有发生过ECC错误； 'b1：发生过ECC错误；对应ecc_clr配置才能清除该历史记录；
  [13] CPU1_DCACHE_DATA_ECCSB_INFO_REC — CPU1 DCACHE data ECC信息状态记录，单比特错误；
  [12] CPU1_DCACHE_TAG_ECCSB_INFO_REC — CPU1 DCACHE TAG ECC信息状态记录，单比特错误；
  [11] CPU1_ICACHE_DATA_ECCSB_INFO_REC — CPU1 ICACHE data ECC信息状态记录，单比特错误；
  [10] CPU1_ICACHE_TAG_ECCSB_INFO_REC — CPU1 ICACHE TAG ECC信息状态记录，单比特错误；
  [9] CPU1_D1TCM_ECCSB_INFO_REC — cpu1 D1TCM ECC信息历史记录，单比特错误； 'b0：没有发生过ECC错误； 'b1：发生过ECC错误； 对应ecc_clr配置才能清除该历史记录；
  [8] CPU1_D0TCM_ECCSB_INFO_REC — cpu1 D0TCM ECC信息历史记录，单比特错误； 'b0：没有发生过ECC错误； 'b1：发生过ECC错误； 对应ecc_clr配置才能清除该历史记录；
  [7] CPU1_ITCM_ECCSB_INFO_REC — cpu1 ITCM ECC信息历史记录，单比特错误； 'b0：没有发生过ECC错误； 'b1：发生过ECC错误； 对应ecc_clr配置才能清除该历史记录；
  [6] CPU0_DCACHE_DATA_ECCSB_INFO_REC — CPU0 DCACHE data ECC信息状态记录，单比特错误；
  [5] CPU0_DCACHE_TAG_ECCSB_INFO_REC — CPU0 DCACHE TAG ECC信息状态记录，单比特错误；
  [4] CPU0_ICACHE_DATA_ECCSB_INFO_REC — CPU0 ICACHE data ECC信息状态记录，单比特错误；
  [3] CPU0_ICACHE_TAG_ECCSB_INFO_REC — CPU0 ICACHE TAG ECC信息状态记录，单比特错误；
  [2] CPU0_D1TCM_ECCSB_INFO_REC — CPU0 D1TCM ECC信息历史记录，单比特错误； 'b0：没有发生过ECC错误； 'b1：发生过ECC错误； 对应ecc_clr配置才能清除该历史记录；
  [1] CPU0_D0TCM_ECCSB_INFO_REC — CPU0 D0TCM ECC信息历史记录，单比特错误； 'b0：没有发生过ECC错误； 'b1：发生过ECC错误； 对应ecc_clr配置才能清除该历史记录；
  [0] CPU0_ITCM_ECCSB_INFO_REC — CPU0 ITCM ECC信息历史记录，单比特错误； 'b0：没有发生过ECC错误； 'b1：发生过ECC错误； 对应ecc_clr配置才能清除该历史记录；
0x1D4 ECC_INFO_MB_REC ro
  [20] DFLASH_MAIN_ECCMB_INFO_REC — DFlash main array ECC信息历史记录，多比特错误； 'b0：没有发生过ECC错误； 'b1：发生过ECC错误； 对应ecc_clr配置才能清除该历史记录；
  [19] DFLASH_NVR_ECCMB_INFO_REC — Flash NVR ECC信息历史记录，多比特错误； 'b0：没有发生过ECC错误； 'b1：发生过ECC错误； 对应ecc_clr配置才能清除该历史记录；
  [18] PFLASH_MAIN_ECCMB_INFO_REC — PFlash0 main array ECC信息历史记录，多比特错误； 'b0：没有发生过ECC错误； 'b1：发生过ECC错误； 对应ecc_clr配置才能清除该历史记录；
  [17] PFLASH_NVR_ECCMB_INFO_REC — Flash NVR ECC信息历史记录，多比特错误； 'b0：没有发生过ECC错误； 'b1：发生过ECC错误； 对应ecc_clr配置才能清除该历史记录；
  [16] CAN0_ECCMB_INFO_REC — AXI SRAM0 ECC信息历史记录，多比特错误；'b0：没有发生过ECC错误；'b1：发生过ECC错误；对应ecc_clr配置才能清除该历史记录；
  [15] XSRAM1_ECCMB_INFO_REC — AXI SRAM1 ECC信息历史记录，多比特错误； 'b0：没有发生过ECC错误； 'b1：发生过ECC错误； 对应ecc_clr配置才能清除该历史记录；
  [14] XSRAM0_ECCMB_INFO_REC — AXI SRAM0 ECC信息历史记录，多比特错误； 'b0：没有发生过ECC错误； 'b1：发生过ECC错误； 对应ecc_clr配置才能清除该历史记录；
  [13] CPU1_DCACHE_DATA_ECCMB_INFO_REC — CPU1 DCACHE data ECC信息状态记录，多比特错误；
  [12] CPU1_DCACHE_TAG_ECCMB_INFO_REC — CPU1 DCACHE TAG ECC信息状态记录，多比特错误；
  [11] CPU1_ICACHE_DATA_ECCMB_INFO_REC — CPU1 ICACHE data ECC信息状态记录，多比特错误；
  [10] CPU1_ICACHE_TAG_ECCMB_INFO_REC — CPU1 ICACHE TAG ECC信息状态记录，多比特错误；
  [9] CPU1_D1TCM_ECCMB_INFO_REC — cpu1 D1TCM ECC信息历史记录，多比特错误； 'b0：没有发生过ECC错误； 'b1：发生过ECC错误； 对应ecc_clr配置才能清除该历史记录；
  [8] CPU1_D0TCM_ECCMB_INFO_REC — cpu1 D0TCM ECC信息历史记录，多比特错误；'b0：没有发生过ECC错误；'b1：发生过ECC错误；对应ecc_clr配置才能清除该历史记录；
  [7] CPU1_ITCM_ECCMB_INFO_REC — cpu1 ITCM ECC信息历史记录，多比特错误； 'b0：没有发生过ECC错误； 'b1：发生过ECC错误； 对应ecc_clr配置才能清除该历史记录；
  [6] CPU0_DCACHE_DATA_ECCMB_INFO_REC — CPU0 DCACHE data ECC信息状态记录，多比特错误；
  [5] CPU0_DCACHE_TAG_ECCMB_INFO_REC — CPU0 DCACHE TAG ECC信息状态记录，多比特错误；
  [4] CPU0_ICACHE_DATA_ECCMB_INFO_REC — CPU0 ICACHE data ECC信息状态记录，多比特错误；
  [3] CPU0_ICACHE_TAG_ECCMB_INFO_REC — CPU0 ICACHE TAG ECC信息状态记录，多比特错误；
  [2] CPU0_D1TCM_ECCMB_INFO_REC — CPU0 D1TCM ECC信息历史记录，多比特错误； 'b0：没有发生过ECC错误； 'b1：发生过ECC错误； 对应ecc_clr配置才能清除该历史记录；
  [1] CPU0_D0TCM_ECCMB_INFO_REC — CPU0 D0TCM ECC信息历史记录，多比特错误； 'b0：没有发生过ECC错误； 'b1：发生过ECC错误； 对应ecc_clr配置才能清除该历史记录；
  [0] CPU0_ITCM_ECCMB_INFO_REC — CPU0 ITCM ECC信息历史记录，多比特错误； 'b0：没有发生过ECC错误； 'b1：发生过ECC错误； 对应ecc_clr配置才能清除该历史记录；
0x1D8 ECC_ADDR_SB_REC ro
  [31:0] CPU0_ITCM_ECCSB_ADDR_REC — CPU itcm ECC单比特错误地址，锁定第一次上报值
0x1DC ECC_ADDR_SB_REC_1 ro
  [31:0] CPU0_D0TCM_ECCSB_ADDR_REC — CPU d0tcm ECC单比特错误地址，锁定第一次上报值
0x1E0 ECC_ADDR_SB_REC_2 ro
  [31:0] CPU0_D1TCM_ECCSB_ADDR_REC — CPU d1tcm ECC单比特错误地址，锁定第一次上报值
0x1E4 ECC_ADDR_SB_REC_3 ro
  [31:0] CPU0_ICACHE_TAG_ECCSB_ADDR_REC — CPU icache ECC单bit错误地址，只有22bit有效，且cache无法区分tag/data；锁定第一次上报值；
0x1E8 ECC_ADDR_SB_REC_4 ro
  [31:0] CPU0_ICACHE_DATA_ECCSB_ADDR_REC — CPU icache ECC单bit错误地址，只有22bit有效，且cache无法区分tag/data；锁定第一次上报值；
0x1EC ECC_ADDR_SB_REC_5 ro
  [31:0] CPU0_DCACHE_TAG_ECCSB_ADDR_REC — CPU dcache ECC单bit错误地址，只有22bit有效，且cache无法区分tag/data；锁定第一次上报值；
0x1F0 ECC_ADDR_SB_REC_6 ro
  [31:0] CPU0_DCACHE_DATA_ECCSB_ADDR_REC — CPU dcache ECC单bit错误地址，只有22bit有效，且cache无法区分tag/data；锁定第一次上报值；
0x1F4 ECC_ADDR_SB_REC_7 ro
  [31:0] CPU1_ITCM_ECCSB_ADDR_REC — CPU itcm ECC单比特错误地址，锁定第一次上报值
0x1F8 ECC_ADDR_SB_REC_8 ro
  [31:0] CPU1_D0TCM_ECCSB_ADDR_REC — CPU d0tcm ECC单比特错误地址，锁定第一次上报值
0x1FC ECC_ADDR_SB_REC_9 ro
  [31:0] CPU1_D1TCM_ECCSB_ADDR_REC — CPU d1tcm ECC单比特错误地址，锁定第一次上报值
0x200 ECC_ADDR_SB_REC_10 ro
  [31:0] CPU1_ICACHE_TAG_ECCSB_ADDR_REC — CPU icache ECC单bit错误地址，只有22bit有效，且cache无法区分tag/data；锁定第一次上报值；
0x204 ECC_ADDR_SB_REC_11 ro
  [31:0] CPU1_ICACHE_DATA_ECCSB_ADDR_REC — CPU icache ECC单bit错误地址，只有22bit有效，且cache无法区分tag/data；锁定第一次上报值；
0x208 ECC_ADDR_SB_REC_12 ro
  [31:0] CPU1_DCACHE_TAG_ECCSB_ADDR_REC — CPU dcache ECC单bit错误地址，只有22bit有效，且cache无法区分tag/data；锁定第一次上报值；
0x20C ECC_ADDR_SB_REC_13 ro
  [31:0] CPU1_DCACHE_DATA_ECCSB_ADDR_REC — CPU dcache ECC单bit错误地址，只有22bit有效，且cache无法区分tag/data；锁定第一次上报值；
0x210 ECC_ADDR_SB_REC_14 ro
  [31:0] XSRAM0_ECCSB_ADDR_REC — SRAM0 ECC单比特错误地址，锁定第一次上报值
0x214 ECC_ADDR_SB_REC_15 ro
  [31:0] XSRAM1_ECCSB_ADDR_REC — SRAM1 ECC单比特错误地址，锁定第一次上报值
0x218 ECC_ADDR_SB_REC_16 ro
  [31:0] CAN0_ECCSB_ADDR_REC — CAN0 ECC单比特错误地址，锁定第一次上报值
0x21C ECC_ADDR_SB_REC_17 ro
  [31:0] DFLASH_NVR_ECCSB_ADDR_REC — dFlash NVR ECC单比特错误地址，锁定第一次上报值
0x220 ECC_ADDR_SB_REC_18 ro
  [31:0] DFLASH_MAIN_ECCSB_ADDR_REC — dFlash Main ECC单比特错误地址，锁定第一次上报值
0x224 ECC_ADDR_SB_REC_19 ro
  [31:0] PFLASH_NVR_ECCSB_ADDR_REC — pFlash0 NVR ECC单比特错误地址，锁定第一次上报值
0x228 ECC_ADDR_SB_REC_20 ro
  [31:0] PFLASH_MAIN_ECCSB_ADDR_REC — pFlash0 Main ECC单比特错误地址，锁定第一次上报值
0x22C ECC_ADDR_MB_REC ro
  [31:0] CPU0_ITCM_ECCMB_ADDR_REC — CPU itcm ECC多比特错误地址，锁定第一次上报值
0x230 ECC_ADDR_MB_REC_1 ro
  [31:0] CPU0_D0TCM_ECCMB_ADDR_REC — CPU d0tcm ECC多比特错误地址，锁定第一次上报值
0x234 ECC_ADDR_MB_REC_2 ro
  [31:0] CPU0_D1TCM_ECCMB_ADDR_REC — CPU d1tcm ECC多比特错误地址，锁定第一次上报值
0x238 ECC_ADDR_MB_REC_3 ro
  [31:0] CPU0_ICACHE_TAG_ECCMB_ADDR_REC — CPU icache ECC单bit错误地址，只有22bit有效，且cache无法区分tag/data；锁定第一次上报值；
0x23C ECC_ADDR_MB_REC_4 ro
  [31:0] CPU0_ICACHE_DATA_ECCMB_ADDR_REC — CPU icache ECC单bit错误地址，只有22bit有效，且cache无法区分tag/data；锁定第一次上报值；
0x240 ECC_ADDR_MB_REC_5 ro
  [31:0] CPU0_DCACHE_TAG_ECCMB_ADDR_REC — CPU dcache ECC单bit错误地址，只有22bit有效，且cache无法区分tag/data；锁定第一次上报值；
0x244 ECC_ADDR_MB_REC_6 ro
  [31:0] CPU0_DCACHE_DATA_ECCMB_ADDR_REC — CPU dcache ECC单bit错误地址，只有22bit有效，且cache无法区分tag/data；锁定第一次上报值；
0x248 ECC_ADDR_MB_REC_7 ro
  [31:0] CPU1_ITCM_ECCMB_ADDR_REC — CPU itcm ECC多比特错误地址，锁定第一次上报值
0x24C ECC_ADDR_MB_REC_8 ro
  [31:0] CPU1_D0TCM_ECCMB_ADDR_REC — CPU d0tcm ECC多比特错误地址，锁定第一次上报值
0x250 ECC_ADDR_MB_REC_9 ro
  [31:0] CPU1_D1TCM_ECCMB_ADDR_REC — CPU d1tcm ECC多比特错误地址，锁定第一次上报值
0x254 ECC_ADDR_MB_REC_10 ro
  [31:0] CPU1_ICACHE_TAG_ECCMB_ADDR_REC — CPU icache ECC单bit错误地址，只有22bit有效，且cache无法区分tag/data；锁定第一次上报值；
0x258 ECC_ADDR_MB_REC_11 ro
  [31:0] CPU1_ICACHE_DATA_ECCMB_ADDR_REC — CPU icache ECC单bit错误地址，只有22bit有效，且cache无法区分tag/data；锁定第一次上报值；
0x25C ECC_ADDR_MB_REC_12 ro
  [31:0] CPU1_DCACHE_TAG_ECCMB_ADDR_REC — CPU dcache ECC单bit错误地址，只有22bit有效，且cache无法区分tag/data；锁定第一次上报值；
0x260 ECC_ADDR_MB_REC_13 ro
  [31:0] CPU1_DCACHE_DATA_ECCMB_ADDR_REC — CPU dcache ECC单bit错误地址，只有22bit有效，且cache无法区分tag/data；锁定第一次上报值；
0x264 ECC_ADDR_MB_REC_14 ro
  [31:0] XSRAM0_ECCMB_ADDR_REC — SRAM0 ECC多比特错误地址，锁定第一次上报值
0x268 ECC_ADDR_MB_REC_15 ro
  [31:0] XSRAM1_ECCMB_ADDR_REC — SRAM1 ECC多比特错误地址，锁定第一次上报值
0x26C ECC_ADDR_MB_REC_16 ro
  [31:0] CAN0_ECCMB_ADDR_REC — CAN0 ECC多比特错误地址，锁定第一次上报值
0x270 ECC_ADDR_MB_REC_17 ro
  [31:0] DFLASH_NVR_ECCMB_ADDR_REC — dFlash NVR ECC多比特错误地址，锁定第一次上报值
0x274 ECC_ADDR_MB_REC_18 ro
  [31:0] DFLASH_MAIN_ECCMB_ADDR_REC — dFlash Main ECC多比特错误地址，锁定第一次上报值
0x278 ECC_ADDR_MB_REC_19 ro
  [31:0] PFLASH_NVR_ECCMB_ADDR_REC — pFlash0 NVR ECC多比特错误地址，锁定第一次上报值
0x27C ECC_ADDR_MB_REC_20 ro
  [31:0] PFLASH_MAIN_ECCMB_ADDR_REC — pFlash0 Main ECC多比特错误地址，锁定第一次上报值
0x280 TESTPIN
  [31:16] SYSC_TESTPIN1_SEL — 功能模式各模块测试管脚选择
  [15:0] SYSC_TESTPIN0_SEL — 功能模式各模块测试管脚选择
0x284 TESTPIN_1
  [31:16] SYSC_TESTPIN3_SEL — 功能模式各模块测试管脚选择
  [15:0] SYSC_TESTPIN2_SEL — 功能模式各模块测试管脚选择
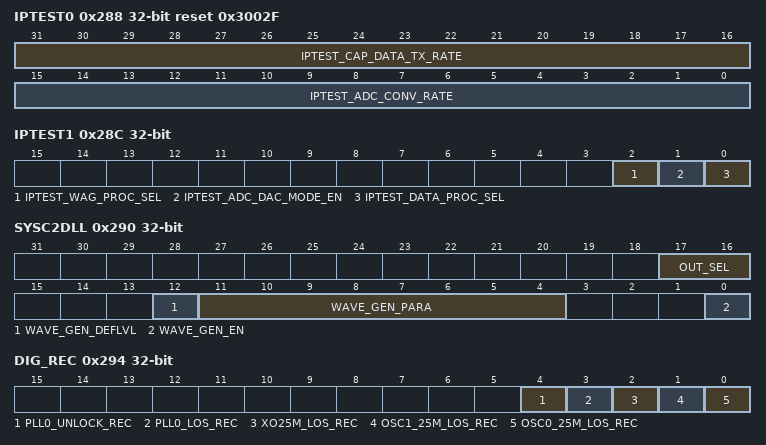
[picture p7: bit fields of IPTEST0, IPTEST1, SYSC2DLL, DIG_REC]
0x288 IPTEST0 reset 0x3002F
  [31:16] IPTEST_CAP_DATA_TX_RATE — 产生对外发数使能的分频比。取值范围[1, 65535]；默认值为3，即按SARC工作时钟的1/4速率发数。
  [15:0] IPTEST_ADC_CONV_RATE — ADC转换触发信号的产生周期（SARC工作时钟周期为单位）。取值范围[47, 65535];默认值为47，即转换周期为48个SARC工作时钟。
0x28C IPTEST1
  [2] IPTEST_WAG_PROC_SEL — ADC采样数据有效指示信号选择； 'b0: 选择ADC采样后的数据有效指示； 'b1: 选择WAG后的数据有效指示；默认值为0.
  [1] IPTEST_ADC_DAC_MODE_EN — IPTEST数采模式使能； 'b0: IPTEST adc/dac数采模式关闭； 'b1: IPTEST adc/dac数采模式打开；默认值为0。
  [0] IPTEST_DATA_PROC_SEL — ADC采样数据保存选择； 'b0: ADC数据存储到RAM中，采完数再发送； 'b1: ADC数据不存储在RAM中，SARC数据输出到PIN管脚；默认值为0.
0x290 SYSC2DLL
  [17:16] OUT_SEL — DLL输出选择信号； 2'b00:输出dll11~dll0 2'b01：输出dll23~dll12 2'b10：输出dll35~dll24 2'b11:同2'b00；
  [12] WAVE_GEN_DEFLVL — DLL iptest测试时默认电平配置； 'b0：默认电平为低电平； 'b1：默认电平为高电平；
  [11:4] WAVE_GEN_PARA — DLL iptest测试时的变频参数；配置为N表示（N+1）分频；
  [0] WAVE_GEN_EN — DLL iptest测试时的变频使能; 'b0：输出即为cfg_sysc2dll0_wave_gen_deflvl； 'b1：输出为cfg_sysc2dll0_wave_gen_para变频后的信号；
0x294 DIG_REC
  [4] PLL0_UNLOCK_REC — PLL0失锁历史记录软件写1清。
  [3] PLL0_LOS_REC — PLL0时钟丢失历史记录软件写1清。
  [2] XO25M_LOS_REC — XO25M时钟丢失历史记录软件写1清。
  [1] OSC1_25M_LOS_REC — OSC1_25M时钟丢失历史记录软件写1清。
  [0] OSC0_25M_LOS_REC — OSC0_25M时钟丢失历史记录软件写1清。
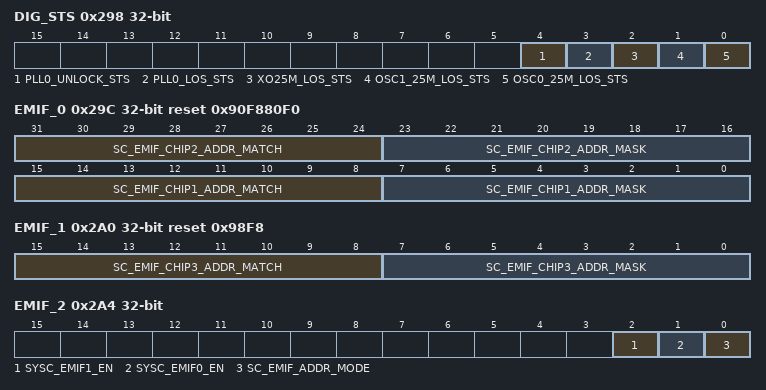
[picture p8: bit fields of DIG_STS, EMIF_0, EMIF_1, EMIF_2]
0x298 DIG_STS ro
  [4] PLL0_UNLOCK_STS — PLL0失锁历史状态
  [3] PLL0_LOS_STS — PLL0时钟丢失历史状态
  [2] XO25M_LOS_STS — XO25M时钟丢失历史状态
  [1] OSC1_25M_LOS_STS — OSC1_25M时钟丢失历史状态
  [0] OSC0_25M_LOS_STS — OSC0_25M时钟丢失历史状态
0x29C EMIF_0 reset 0x90F880F0
  [31:24] SC_EMIF_CHIP2_ADDR_MATCH — emif chip2的匹配地址配置
  [23:16] SC_EMIF_CHIP2_ADDR_MASK — emif chip2的地址掩码配置 即（act_addr & mask）== match，即认为匹配上。
  [15:8] SC_EMIF_CHIP1_ADDR_MATCH — emif chip1的匹配地址配置
  [7:0] SC_EMIF_CHIP1_ADDR_MASK — emif chip1的地址掩码配置 即（act_addr & mask）== match，即认为匹配上。
0x2A0 EMIF_1 reset 0x98F8
  [15:8] SC_EMIF_CHIP3_ADDR_MATCH — emif chip3的匹配地址配置
  [7:0] SC_EMIF_CHIP3_ADDR_MASK — emif chip3的地址掩码配置 即（act_addr & mask）== match，即认为匹配上。
0x2A4 EMIF_2
  [2] SYSC_EMIF1_EN — 是否允许axi总线访问emif1 0：不允许 1：允许
  [1] SYSC_EMIF0_EN — 是否允许axi总线访问emif0 0：不允许 1：允许
  [0] SC_EMIF_ADDR_MODE — emif-SMC地址模式 'b0:
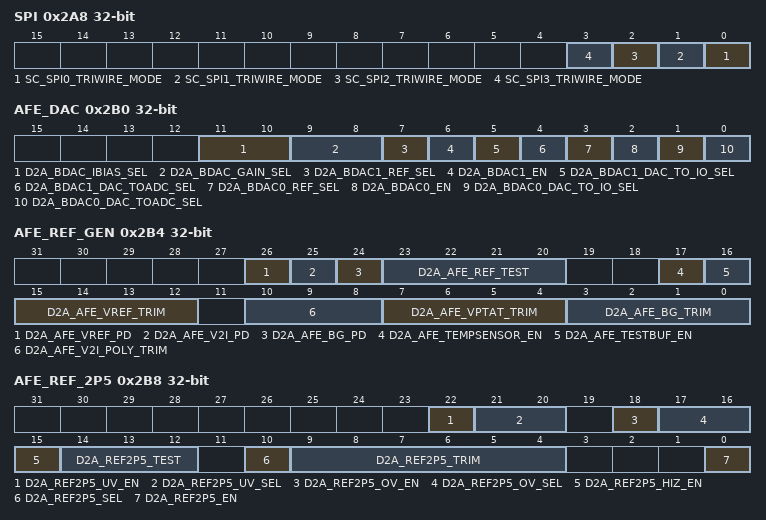
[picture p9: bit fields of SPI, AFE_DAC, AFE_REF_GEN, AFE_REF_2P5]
0x2A8 SPI
  [n] SC_SPI{n}_TRIWIRE_MODE (n=0..3) — spi{n}三线/四线模式配置 1'b1:spi采样三线模式； 1'b0:spi采用四线模式；
0x2AC AFE_COMPARATOR
  [1:0] D2A_CMPSS_IBIAS_SEL — CMPSSbias电流调节。00:1uA（默认值）01:0.5uA10:1.5uA11:2uA
0x2B0 AFE_DAC
  [11:10] D2A_BDAC_IBIAS_SEL — BDACbias电流调节。00:2.5uA（默认值）01:2uA10:3.5uA11:5uA
  [9:8] D2A_BDAC_GAIN_SEL — BDACbuffergain调节，Bit<1>未使用，由Bit<0>控制：Bit<0>=0：gain=1;Bit<0>=1：gain=2;
  [7] D2A_BDAC1_REF_SEL — 同d2a_bdac0_ref_sel
  [6] D2A_BDAC1_EN — 同d2a_bdac0_en
  [5] D2A_BDAC1_DAC_TO_IO_SEL — 同d2a_bdac0_dac_to_io_sel
  [4] D2A_BDAC1_DAC_TOADC_SEL — 同d2a_bdac0_dac_todac_sel
  [3] D2A_BDAC0_REF_SEL — BDAC的dacreference源选择1:内部2.5/1.65refbuffer输入0:PAD输入
  [2] D2A_BDAC0_EN — BDAC使能信号0：不使能，输出高阻1：使能
  [1] D2A_BDAC0_DAC_TO_IO_SEL — BDAC的dac测试控制位0：不进行测试。1：测试模式，dac输出接到io输出。
  [0] D2A_BDAC0_DAC_TOADC_SEL — BDAC的dac测试控制位0：不进行测试。1：测试模式，dac输出接到adc输入。
0x2B4 AFE_REF_GEN
  [26] D2A_AFE_VREF_PD — afe_vrefpowerdown控制信号1'b0：工作；1'b1：不工作；
  [25] D2A_AFE_V2I_PD — afe_v2ipowerdown控制信号1'b0：工作；1'b1：不工作；
  [24] D2A_AFE_BG_PD — afe_bgpowerdown控制信号1'b0：bandgap工作；1'b1：bandgap不工作；
  [23:20] D2A_AFE_REF_TEST — afe_ref_gen模块测试配置:4'b0001：VOUT_TESTBUF（VPTAT经过BUFFER）4'b0010：VPTAT（VPTAT经过BUFFER）4'b0011：IBPN2U_PTAT_TEST4'b0100：IBPN2P5U_POLY_TEST4'b0101：VREF0P554'b1110：REF_PROBEB（VREF1P22经过BUFFER）
  [17] D2A_AFE_TEMPSENSOR_EN — afe_ref_gen温度传感器使能控制信号1'b0：温度传感器不工作；1'b1：温度传感器工作；
  [16] D2A_AFE_TESTBUF_EN — afe_ref_gentestbuf使能控制信号1'b0：testbufdisable;1'b1：testbufenable;
  [15:12] D2A_AFE_VREF_TRIM — AFE侧ref电压trim（tt/55℃）4'b0000：549.9mV4'b0001：545.3mV4'b0010：540.6mV4'b0011：535.9mV4'b0100：531.3mV4'b0101：526.6mV4'b0110：522.0mV4'b0111：517.3mV4'b1000：582.5mV4'b1001：577.9mV4'b1010：573.2mV4'b1011：568.6mV4'b1100：563.9mV4'b1101：559.2mV4'b1110：554.6mV4'b1111：549.9mV
  [10:8] D2A_AFE_V2I_POLY_TRIM — AFE侧poly电流trim（tt/55℃）IBPN2P5U_POLY_TEST电流trim值3'b000：2.480uA3'b001：2.147uA3'b010：1.821uA3'b011：1.492uA3'b100：3.597uA3'b101：3.255uA3'b110：2.936uA3'b111：2.616uA
  [7:4] D2A_AFE_VPTAT_TRIM — AFE侧PTAT电压trim（tt/55℃）4'b0000：821.0mV4'b0001：816.1mV4'b0010：811.1mV4'b0011：806.2mV4'b0100：801.3mV4'b0101：796.3mV4'b0110：791.4mV4'b0111：786.5mV4'b1000：855.4mV4'b1001：850.6mV4'b1010：845.6mV4'b1011：840.7mV4'b1100：835.8mV4'b1101：830.9mV4'b1110：825.9mV4'b1111：821.0mV
  [3:0] D2A_AFE_BG_TRIM — AFE侧Bandgap电压trim（tt/55℃）4'b0000：1221mV4'b0001：1211mV4'b0010：1201mV4'b0011：1191mV4'b0100：1181mV4'b0101：1172mV4'b0110：1162mV4'b0111：1152mV4'b1000：1290mV4'b1001：1280mV4'b1010：1270mV4'b1011：1260mV4'b1100：1251mV4'b1101：1241mV4'b1110：1231mV4'b1111：1221mV
0x2B8 AFE_REF_2P5
  [22] D2A_REF2P5_UV_EN — afe_ref_2p5电压误差超过上边界门限监测使能信号1'b0：disable;1'b1：enable;
  [21:20] D2A_REF2P5_UV_SEL — afe_ref_2p5电压误差低于下边界选择信号2'b00：2.254(default）2'b01：2.1652'b10：2.1132'b11:2.35
  [18] D2A_REF2P5_OV_EN — afe_ref_2p5电压误差超过上边界门限监测使能信号1'b0：disable;1'b1：enable;
  [17:16] D2A_REF2P5_OV_SEL — afe_ref_2p5电压误差超过上边界门限选择信号2'b00：2.747(default）2'b01：2.6632'b10：2.5852'b11:2.835
  [15] D2A_REF2P5_HIZ_EN — afe_ref_2p5电路输出HIZ态控制信号，1'b0：HIZ无效;1'b1：HIZ态生效;
  [14:12] D2A_REF2P5_TEST — afe_ref_test选择信号
  [10] D2A_REF2P5_SEL — afe_ref_2p5电路输出，2.5V和1.65V选择信号1'b0：输出2.5V;1'b1：输出1.65V;
  [9:4] D2A_REF2P5_TRIM — afe_ref_2p5电压trim信号,2.5mV/step；'b00-0000:2500mV；'b00-0001~'b10-0000:2421mV为起点，2.5mV/step递增；'b10-0001~'b11-1111:2502mV为起点，2.5mV/step递增;
  [0] D2A_REF2P5_EN — afe_ref_2p5使能控制信号1'b0：disable;1'b1：enable;
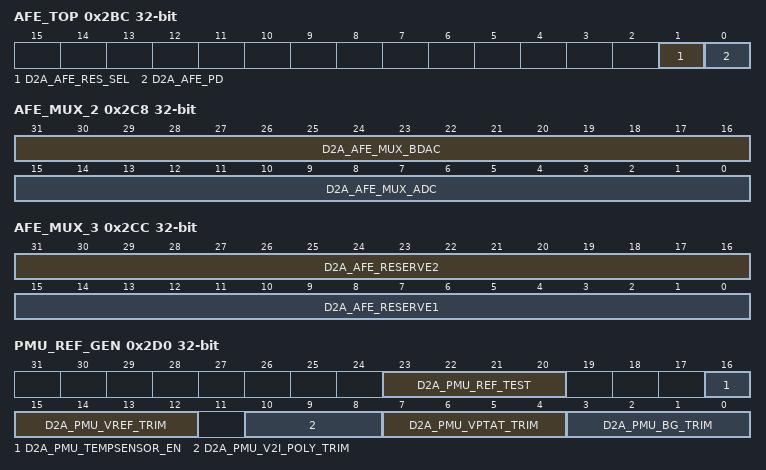
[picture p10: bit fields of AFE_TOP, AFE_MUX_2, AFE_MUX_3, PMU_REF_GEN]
0x2BC AFE_TOP
  [1] D2A_AFE_RES_SEL — BG里的RES使能控制模块=0enable=1disable
  [0] D2A_AFE_PD — afe使能控制模块=0enable=1disable
0x2C0 AFE_MUX
  [0] D2A_AFE_MUX_EN — afe_core顶层AMUX开关使能信号1'b0:disable1'b1:enable
0x2C4 AFE_MUX_1
  [28:0] D2A_AFE_MUX_CMPSS — <28:0>:afe_core顶层CMP,BG,REF2P5AMUX开关控制，为1时连通，为0时断开;<0>:CMP1测试信号选通到PADA7；<1>:CMP2测试信号选通到PADA7；<2>:CMP3测试信号选通到PADA7；<3>:CMP4测试信号选通到PADA7；<4>:CMP5测试信号选通到PADA7；<5>:CMP6测试信号选通到PADA7；<6>:CMP7测试信号选通到PADA7<7>:CMP8测试信号选通到PADA7；<8>:CMP9测试信号选通到PADA7；<9>:CMP10测试信号选通到PADA7；<10>:CMP11测试信号选通到PADA7；<11>:CMP1_DAC测试信号选通选通到PADA7；<12>:CMP2_DAC测试信号选通选通到PADA7；<13>:CMP3_DAC测试信号选通选通到PADA7；<14>:CMP4_DAC测试信号选通选通到PADA7；<15>:CMP5_DAC测试信号选通选通到PADA7；<16>:CMP6_DAC测试信号选通选通到PADA7；<17>:CMP7_DAC测试信号选通选通到PADA7；<18>:CMP8_DAC测试信号选通选通到PADA7；<19>:CMP9_DAC测试信号选通选通到PADA7；<20>:CMP10_DAC测试信号选通选通到PADA7；<21>:CMP11_DAC测试信号选通选通到PADA7；<22>:BG检测信号选通到PADVREFHIA；<23>:REF2P5检测信号选通到PADVREFHIA；<24>:BDACA检测信号选通到PADA1；<25>:BDACB检测信号选通到PADB1；<26>:PADC4_GPIO228与AFE内部的连通；<27>:PADC3_GPIO228与AFE内部的连通；<28>:unuse
0x2C8 AFE_MUX_2
  [31:16] D2A_AFE_MUX_BDAC — unused
  [15:0] D2A_AFE_MUX_ADC — unused
0x2CC AFE_MUX_3
  [31:16] D2A_AFE_RESERVE2 — unused
  [15:0] D2A_AFE_RESERVE1 — unused
0x2D0 PMU_REF_GEN
  [23:20] D2A_PMU_REF_TEST — pmu_ref_gen模块内部信号检测:4'b0010：VPTAT4'b0011：IBPN2U_PTAT_TEST4'b0100：IBPN2P5U_POLY_TEST4'b0101：VREF0P554'b0110：REF_PROBEB（VREF1P22经过buffer的输出）
  [16] D2A_PMU_TEMPSENSOR_EN — 0：温度传感器不工作1：温度传感器输出VPTAT电压
  [15:12] D2A_PMU_VREF_TRIM — vref参考电压(@55℃)trim：4'b0000：549.9mV4'b0001：545.3mV4'b0010：540.6mV4'b0011：535.9mV4'b0100：531.3mV4'b0101：526.6mV4'b0110：522.0mV4'b0111：517.3mV4'b1000：582.5mV4'b1001：577.9mV4'b1010：573.2mV4'b1011：568.6mV4'b1100：563.9mV4'b1101：559.2mV4'b1110：554.6mV4'b1111：549.9mV
  [10:8] D2A_PMU_V2I_POLY_TRIM — v2i_poly电流(@55℃)trim:IBPN2P5U_POLY_TEST电流trim值3'b000：2.480uA3'b001：2.147uA3'b010：1.821uA3'b011：1.492uA3'b100：3.597uA3'b101：3.255uA3'b110：2.936uA3'b111：2.616uA
  [7:4] D2A_PMU_VPTAT_TRIM — 温度检测输出电压(@55℃)trim:4'b0000：821.0mV4'b0001：816.1mV4'b0010：811.1mV4'b0011：806.2mV4'b0100：801.3mV4'b0101：796.3mV4'b0110：791.4mV4'b0111：786.5mV4'b1000：855.4mV4'b1001：850.6mV4'b1010：845.6mV4'b1011：840.7mV4'b1100：835.8mV4'b1101：830.9mV4'b1110：825.9mV4'b1111：821.0mV
  [3:0] D2A_PMU_BG_TRIM — VBG电压trim(@55℃)：4'b0000：1221mV4'b0001：1211mV4'b0010：1201mV4'b0011：1191mV4'b0100：1181mV4'b0101：1172mV4'b0110：1162mV4'b0111：1152mV4'b1000：1290mV4'b1001：1280mV4'b1010：1270mV4'b1011：1260mV4'b1100：1251mV4'b1101：1241mV4'b1110：1231mV4'b1111：1221mV
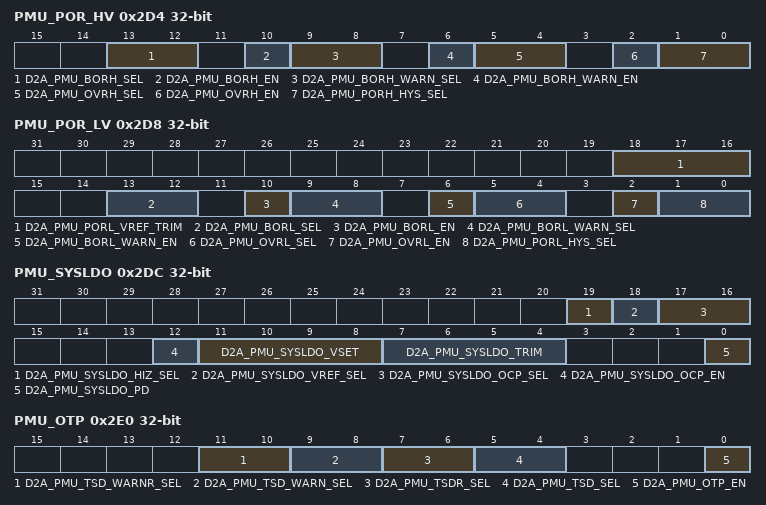
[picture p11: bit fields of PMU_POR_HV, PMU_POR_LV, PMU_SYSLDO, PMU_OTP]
0x2D4 PMU_POR_HV
  [13:12] D2A_PMU_BORH_SEL — 3.3V电压域欠压电压档位：00：2.895(default)01：2.69510：2.79111：2.995
  [10] D2A_PMU_BORH_EN — 3.3V电压域欠压模块使能：0：欠压模块使能关闭1：欠压模块使能开启
  [9:8] D2A_PMU_BORH_WARN_SEL — 3.3V电压域欠压告警电压档位：00：2.994(default)01：2.79210：2.89511：3.088
  [6] D2A_PMU_BORH_WARN_EN — 3.3V电压域欠压告警模块使能：0：欠压告警使能关闭1：欠压告警使能开启
  [5:4] D2A_PMU_OVRH_SEL — 3.3V电压域过压检测电压档位：00：3.598(default)01：3.50210：3.69911：3.734
  [2] D2A_PMU_OVRH_EN — 3.3V电压域OVR模块使能信号：0：过压检测关闭1：过压检测开启
  [1:0] D2A_PMU_PORH_HYS_SEL — 3.3V电压域POR下电电压档位（即迟滞大小选择）：2'b00：2.705(default)2'b01：2.4992'b10：2.5982'b11：2.801
0x2D8 PMU_POR_LV
  [18:16] D2A_PMU_PORL_VREF_TRIM — noUse
  [13:12] D2A_PMU_BORL_SEL — 1.1V电压域欠压电压档位：00：0.8935(default)01：0.835510：0.944511：1.002
  [10] D2A_PMU_BORL_EN — 1.1V电压域欠压模块使能：0：欠压模块使能关闭1：欠压模块使能开启
  [9:8] D2A_PMU_BORL_WARN_SEL — 1.1V电压域欠压告警电压档位：00：0.9925(default)01：0.936510：1.04611：1.106
  [6] D2A_PMU_BORL_WARN_EN — 1.1V电压域欠压告警模块使能：0：欠压告警使能关闭1：欠压告警使能开启
  [5:4] D2A_PMU_OVRL_SEL — 1.1V电压域过压检测电压档位：00：1.261(default)01：1.20810：1.31811：1.364
  [2] D2A_PMU_OVRL_EN — 1.1V电压域OVR模块使能信号：0：过压检测关闭1：过压检测开启
  [1:0] D2A_PMU_PORL_HYS_SEL — 1.1V电压域POR下电电压档位（即迟滞大小选择）：2'b00：0.6995(default)2'b01：0.64452'b10：0.75352'b11：0.8115
0x2DC PMU_SYSLDO
  [19] D2A_PMU_SYSLDO_HIZ_SEL — 0：SYSLDO_HIZ=0结合d2a_pmu_sysldo_pd=1配置使sysldo处于高阻态1：SYSLDO_HIZ=1结合d2a_pmu_sysldo_pd=1配置使sysldo处于下拉态
  [18] D2A_PMU_SYSLDO_VREF_SEL — 0：SYSLDO_VREF_SEL=0，SYSLDO_SS_EN=1sysldo为缓启动模式1：SYSLDO_VREF_SEL=1，SYSLDO_SS_EN=0sysldo为快启动模块
  [17:16] D2A_PMU_SYSLDO_OCP_SEL — 00：577.5mA01：502.5mA10：722.5mA11：652.5mA
  [12] D2A_PMU_SYSLDO_OCP_EN — 0：过流保护功能关闭1：过流保护功能开启
  [11:8] D2A_PMU_SYSLDO_VSET — sysldoset电压档位：4'b0000：1100mV4'b0001：927.2mV4'b0010：976.4mV4'b0011：1001mV4'b0100：1026mV4'b0101：1050mV4'b0110：1075mV4'b0111：1125mV4'b1000：1150mV4'b1001：1175mV4'b1010：1200mV4'b1011：1225mV4'b1100：1250mV4'b1101：1350mV4'b1110：1450mV4'b1111：1550mV
  [7:4] D2A_PMU_SYSLDO_TRIM — sysldo电压trim档位：4'b0000：1099mV4'b0001：1307mV4'b0010：1273mV4'b0011：1240mV4'b0100：1209mV4'b0101：1180mV4'b0110：1152mV4'b0111：1125mV4'b1000：1344mV4'b1001：1075mV4'b1010：1052mV4'b1011：1029mV4'b1100：1008mV4'b1101：987.3mV4'b1110：967.6mV4'b1111：1099mV
  [0] D2A_PMU_SYSLDO_PD — 0：控制sysldo开启1：sysldo不工作
0x2E0 PMU_OTP
  [11:10] D2A_PMU_TSD_WARNR_SEL — 热告警复位档位配置：00：124℃01：119℃10：129℃11：-17℃
  [9:8] D2A_PMU_TSD_WARN_SEL — 热（温度）关闭告警档位配置：00：151℃01：146℃10：156℃11：10℃
  [7:6] D2A_PMU_TSDR_SEL — 热复位档位配置：00：140℃01：135℃10：145℃11：-17℃
  [5:4] D2A_PMU_TSD_SEL — 热（温度）关闭档位配置：00：167℃01：161℃10：173℃11：10℃
  [0] D2A_PMU_OTP_EN — 过温保护模块使能：0：模块不工作1：模块使能
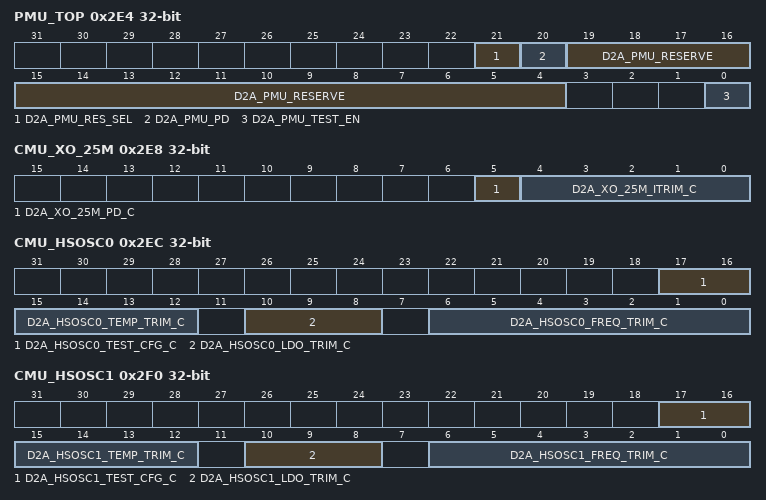
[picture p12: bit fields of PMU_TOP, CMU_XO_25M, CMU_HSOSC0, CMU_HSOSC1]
0x2E4 PMU_TOP
  [21] D2A_PMU_RES_SEL — BG里的RES使能控制模块=0enable=1disable
  [20] D2A_PMU_PD — PMU使能控制模块=0enable=1disable
  [19:4] D2A_PMU_RESERVE — 16位预留寄存器bit<15:0>:noCon
  [0] D2A_PMU_TEST_EN — 顶层test模块使能打开0：关闭pmu模块test通道1：打开pmu模块test通道
0x2E8 CMU_XO_25M
  [5] D2A_XO_25M_PD_C — XO_25MPowerDown信号=1Powerdown=0工作
  [4:0] D2A_XO_25M_ITRIM_C — XO_25M偏置电流选择信号；位控方式<4:0>=[10.20.40.81]mA=1接入；=0断开
0x2EC CMU_HSOSC0
  [17:16] D2A_HSOSC0_TEST_CFG_C — HSOSC测试配置信号，位控制2'b00测试关闭；2'b011.25u电流测试；2'b10LDO1.1V电源测试；2'b11LDO1.1V参考电压测试；
  [15:12] D2A_HSOSC0_TEMP_TRIM_C — HSOSC温度系数选择信号bit[3]=0温度系数逐渐递增；bit[3]=1温度系数逐渐递减；bit[2:0]按每code温度系数递增（bit[3]=0）或递减（bit[3]=1）
  [10:8] D2A_HSOSC0_LDO_TRIM_C — HSOSC内置电源电压选择信号3'b000=1.1V;001~011=1.025V+25m/step100~111=1.125V+25m/step
  [6:0] D2A_HSOSC0_FREQ_TRIM_C — HSOSC频率校正信号：bit[5:0]每增加1code，频率增大150KHz；bit[6]=0频率由中间频率往上递增至最大频率；bit[6]=1频率由最小频率往上递增至中间频率；
0x2F0 CMU_HSOSC1
  [17:16] D2A_HSOSC1_TEST_CFG_C — HSOSC测试配置信号，位控制2'b00测试关闭；2'b011.25u电流测试；2'b10LDO1.1V电源测试；2'b11LDO1.1V参考电压测试；
  [15:12] D2A_HSOSC1_TEMP_TRIM_C — HSOSC温度系数选择信号bit[3]=0温度系数逐渐递增；bit[3]=1温度系数逐渐递减；bit[2:0]按每code温度系数递增（bit[3]=0）或递减（bit[3]=1）
  [10:8] D2A_HSOSC1_LDO_TRIM_C — HSOSC内置电源电压选择信号3'b000=1.1V;001~011=1.025V+25m/step100~111=1.125V+25m/step
  [6:0] D2A_HSOSC1_FREQ_TRIM_C — HSOSC频率校正信号：bit[5:0]每增加1code，频率增大150KHz；bit[6]=0频率由中间频率往上递增至最大频率；bit[6]=1频率由最小频率往上递增至中间频率；
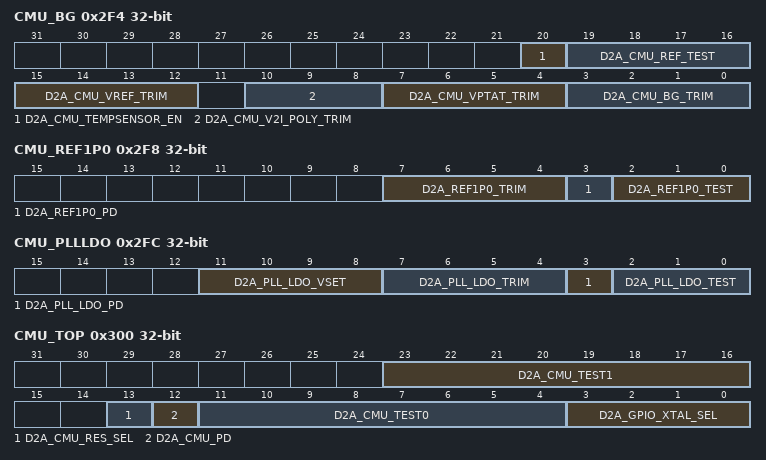
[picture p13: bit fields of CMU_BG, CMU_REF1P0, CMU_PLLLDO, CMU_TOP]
0x2F4 CMU_BG
  [20] D2A_CMU_TEMPSENSOR_EN — 0：温度传感器不工作1：温度传感器输出VPTAT电压
  [19:16] D2A_CMU_REF_TEST — cmu_ref_gen模块内部信号检测:4'b0010：VPTAT4'b0011：IBPN2U_PTAT_TEST4'b0100：IBPN2P5U_POLY_TEST4'b0101：VREF0P554'b0110：REF_PROBEB（VREF1P22经过buffer的输出）
  [15:12] D2A_CMU_VREF_TRIM — vref参考电压(@55℃)trim：4'b0000：549.9mV4'b0001：545.3mV4'b0010：540.6mV4'b0011：535.9mV4'b0100：531.3mV4'b0101：526.6mV4'b0110：522.0mV4'b0111：517.3mV4'b1000：582.5mV4'b1001：577.9mV4'b1010：573.2mV4'b1011：568.6mV4'b1100：563.9mV4'b1101：559.2mV4'b1110：554.6mV4'b1111：549.9mV
  [10:8] D2A_CMU_V2I_POLY_TRIM — v2i_poly电流(@55℃)trim:IBPN2P5U_POLY_TEST电流trim值3'b000：2.480uA3'b001：2.147uA3'b010：1.821uA3'b011：1.492uA3'b100：3.597uA3'b101：3.255uA3'b110：2.936uA3'b111：2.616uA
  [7:4] D2A_CMU_VPTAT_TRIM — 温度检测输出电压(@55℃)trim:4'b0000：821.0mV4'b0001：816.1mV4'b0010：811.1mV4'b0011：806.2mV4'b0100：801.3mV4'b0101：796.3mV4'b0110：791.4mV4'b0111：786.5mV4'b1000：855.4mV4'b1001：850.6mV4'b1010：845.6mV4'b1011：840.7mV4'b1100：835.8mV4'b1101：830.9mV4'b1110：825.9mV4'b1111：821.0mV
  [3:0] D2A_CMU_BG_TRIM — VBG电压trim(@55℃)：4'b0000：1221mV4'b0001：1211mV4'b0010：1201mV4'b0011：1191mV4'b0100：1181mV4'b0101：1172mV4'b0110：1162mV4'b0111：1152mV4'b1000：1290mV4'b1001：1280mV4'b1010：1270mV4'b1011：1260mV4'b1100：1251mV4'b1101：1241mV4'b1110：1231mV4'b1111：1221mV
0x2F8 CMU_REF1P0
  [7:4] D2A_REF1P0_TRIM — Refbuf1p0电压trim：4'b0000：1000mV4'b0001：1093mV4'b0010：1079mV4'b0011：1065mV4'b0100：1051mV4'b0101：1038mV4'b0110：1025mV4'b0111：1013mV4'b1000：1108mV4'b1001：988.3mV4'b1010：976.6mV4'b1011：965.2mV4'b1100：954mV4'b1101：943.1mV4'b1110：932.4mV4'b1111：1000mV
  [3] D2A_REF1P0_PD — Refbuf1p使能控制模块=0enable=1disable
  [2:0] D2A_REF1P0_TEST — Refbuf1p测试选择信号
0x2FC CMU_PLLLDO
  [11:8] D2A_PLL_LDO_VSET — pll_ldo电压vsetdefaule=1.14'b0000：1103mV4'b0001：928.2mV4'b0010：978.2mV4'b0011：1003mV4'b0100：1028mV4'b0101：1053mV4'b0110：1078mV4'b0111：1128mV4'b1000：1153mV4'b1001：1178mV4'b1010：1203mV4'b1011：1228mV4'b1100：1253mV4'b1101：1353mV4'b1110：1453mV4'b1111：1550mV
  [7:4] D2A_PLL_LDO_TRIM — pll_ldo电压trimdefaule=1.14'b0000：1103mV4'b0001：1312mV4'b0010：1277mV4'b0011：1245mV4'b0100：1214mV4'b0101：1184mV4'b0110：1156mV4'b0111：1129mV4'b1000：1348mV4'b1001：1079mV4'b1010：1055mV4'b1011：1033mV4'b1100：1011mV4'b1101：990.6mV4'b1110：970.8mV4'b1111：1103mV
  [3] D2A_PLL_LDO_PD — pll_ldo使能控制模块=0enable=1disable
  [2:0] D2A_PLL_LDO_TEST — pll_ldo测试选择信号
0x300 CMU_TOP
  [23:16] D2A_CMU_TEST1 — CMU_TOP层公用模拟测试寄存器(高4bit暂未使用)：BIT[0]默认为0为1时CMU_TEST_MIX管脚选通；
  [13] D2A_CMU_RES_SEL — BG里的RES使能控制模块=0enable=1disable
  [12] D2A_CMU_PD — CMU使能控制模块=0enable=1disable
  [11:4] D2A_CMU_TEST0 — CMU_TOP层公用模拟测试寄存器（高4bit暂未使用）：8'b0000000默认关闭；8'b0001000fs_ref1p0_test信号被选择；8'b0001001ref_gen_test信号被选择；8'b0001010pllldo_test信号被选择；8'b0001011hsosc_test信号被选择；8'B0001100clk_OSC_256K_C信号被选择；8'b0001101a2d_clkn_osc_25m_c信号被选择；8'b0001110clk_xo_25m_pll_c信号被选择；
  [3:0] D2A_GPIO_XTAL_SEL — <3:0>:CMU顶层XOUT_25M、XIN_25M、GPIO124、GPIO125开关控制，为1时连通，为0时断开;<0>:输入信号选通到XIN_25M；<1>:输入信号选通到GPIO124；<2>:输入信号选通到XOUT_25M；<3>:输入信号选通到GPIO125；
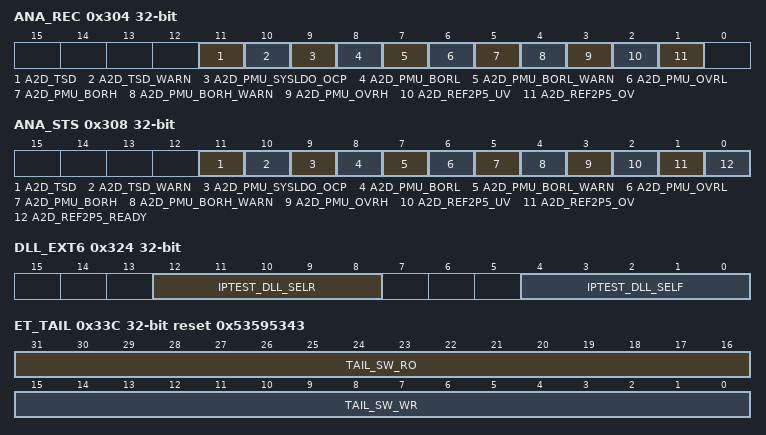
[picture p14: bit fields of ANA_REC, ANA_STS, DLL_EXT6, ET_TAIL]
0x304 ANA_REC
  [11] A2D_TSD — 过温关闭输出指示信号：0：温度未达到指示温度1：温度达到指示温度软件写1清。
  [10] A2D_TSD_WARN — 过温告警输出指示信号：0：温度未达到指示温度1：温软件写1清。
  [9] A2D_PMU_SYSLDO_OCP — ocp过流指示信号0：sysldo未达到指定ocp电流1：sysldo达到指定ocp电流软件写1清。
  [8] A2D_PMU_BORL — 1.1V电压域欠压检测模块1.1V电压输出信号，关闭情况下，输出为0，保证正常工作：0：1.1V电压域电压超过目标值，正常工作1：1.1V电压域电压不超过目标值，欠压指示软件写1清。
  [7] A2D_PMU_BORL_WARN — 1.1V电压域欠压告警检测模块1.1V电压输出信号，关闭情况下，输出为1，保证正常工作：0：1.1V电压域不超过目标值，欠压告警1：1.1V电压域超过目标值，欠压告警解除软件写1清。
  [6] A2D_PMU_OVRL — 1.1V电压域过压检测模块1.1V电压输出信号，关闭情况下，输出为0，保证正常工作：0：1.1V电压域电压不超过目标值，正常工作1：1.1V电压域电压超过目标值，过压指示软件写1清。
  [5] A2D_PMU_BORH — 3.3V电压域欠压检测模块1.1V电压输出信号，关闭情况下，输出为0，保证正常工作：0：3.3V电压域电压超过目标值，正常工作1：3.3V电压域电压不超过目标值，欠压指示软件写1清。
  [4] A2D_PMU_BORH_WARN — 3.3V电压域欠压告警检测模块1.1V电压输出信号，关闭情况下，输出为1，保证正常工作：0：3.3V电压域不超过目标值，欠压告警1：3.3V电压域超过目标值，欠压告警解除软件写1清。
  [3] A2D_PMU_OVRH — 3.3V电压域过压检测模块1.1V电压输出信号，关闭情况下，输出为0，保证正常工作：0：3.3V电压域电压不超过目标值，正常工作1：3.3V电压域电压超过目标值，过压指示软件写1清。
  [2] A2D_REF2P5_UV — afe_ref_2p5电压误差低于下边界门限软件写1清。
  [1] A2D_REF2P5_OV — afe_ref_2p5电压误差超过上边界门限报警信号软件写1清。
0x308 ANA_STS ro
  [11] A2D_TSD — 过温关闭输出指示信号：0：温度未达到指示温度1：温度达到指示温度
  [10] A2D_TSD_WARN — 过温告警输出指示信号：0：温度未达到指示温度1：温
  [9] A2D_PMU_SYSLDO_OCP — ocp过流指示信号0：sysldo未达到指定ocp电流1：sysldo达到指定ocp电流
  [8] A2D_PMU_BORL — 1.1V电压域欠压检测模块1.1V电压输出信号，关闭情况下，输出为0，保证正常工作：0：1.1V电压域电压超过目标值，正常工作1：1.1V电压域电压不超过目标值，欠压指示
  [7] A2D_PMU_BORL_WARN — 1.1V电压域欠压告警检测模块1.1V电压输出信号，关闭情况下，输出为1，保证正常工作：0：1.1V电压域不超过目标值，欠压告警1：1.1V电压域超过目标值，欠压告警解除
  [6] A2D_PMU_OVRL — 1.1V电压域过压检测模块1.1V电压输出信号，关闭情况下，输出为0，保证正常工作：0：1.1V电压域电压不超过目标值，正常工作1：1.1V电压域电压超过目标值，过压指示
  [5] A2D_PMU_BORH — 3.3V电压域欠压检测模块1.1V电压输出信号，关闭情况下，输出为0，保证正常工作：0：3.3V电压域电压超过目标值，正常工作1：3.3V电压域电压不超过目标值，欠压指示
  [4] A2D_PMU_BORH_WARN — 3.3V电压域欠压告警检测模块1.1V电压输出信号，关闭情况下，输出为1，保证正常工作：0：3.3V电压域不超过目标值，欠压告警1：3.3V电压域超过目标值，欠压告警解除
  [3] A2D_PMU_OVRH — 3.3V电压域过压检测模块1.1V电压输出信号，关闭情况下，输出为0，保证正常工作：0：3.3V电压域电压不超过目标值，正常工作1：3.3V电压域电压超过目标值，过压指示
  [2] A2D_REF2P5_UV — afe_ref_2p5电压误差低于下边界门限
  [1] A2D_REF2P5_OV — afe_ref_2p5电压误差超过上边界门限报警信号
  [0] A2D_REF2P5_READY — afe_ref_2p5电路输出稳定标志信号1'b0： 未稳定;1'b1： 稳定;
0x30C DLL_EXT0
  [31:0] D2A_DLL_PWM_SEL0 — DLL0 0~31功能调节寄存器
0x310 DLL_EXT1
  [3:0] D2A_DLL_PWM_SEL1 — DLL0 32~35功能调节寄存器
0x314 DLL_EXT2
  [31:0] D2A_DLL_EN0 — DLL0 0~31使能
0x318 DLL_EXT3
  [3:0] D2A_DLL_EN1 — DLL0 32~35使能
0x31C DLL_EXT4
  [31:0] D2A_DLL_PD0 — DLL0 0~31使能控制模块
0x320 DLL_EXT5
  [3:0] D2A_DLL_PD1 — DLL0 32~35使能控制模块
0x324 DLL_EXT6
  [12:8] IPTEST_DLL_SELR — DLL上升沿延迟级数选择
  [4:0] IPTEST_DLL_SELF — DLL下降沿延迟级数选择
{0x328+4i} DLL_TRIM{i} (i=0..3)
  [31:0] D2A_DLL_FLASH_TRIM{i} — dll flash校准码值,选择delay精度 bit[3:0]: DLL{8i}的falsh trim参数； bit[7:4]: DLL{8i+1}的flash trim参数； ...... bit[31:28]: DLL{8i+7}的flash trim参数
0x338 DLL_TRIM4
  [15:0] D2A_DLL_FLASH_TRIM4 — dll flash校准码值,选择delay精度 bit[3:0]: DLL32的falsh trim参数； bit[7:4]: DLL33的flash trim参数； bit[11:8]: DLL34的flash trim参数； bit[15:12]: DLL35的flash trim参数；
0x33C ET_TAIL reset 0x53595343
  [31:16] TAIL_SW_RO ro — 软件只读上报寄存器，硬件无访问
  [15:0] TAIL_SW_WR — 软件测试读写寄存器，硬件无访问,SYSC的ASICII 码表示
